VERSION 5.7 ;
  NOWIREEXTENSIONATPIN ON ;
  DIVIDERCHAR "/" ;
  BUSBITCHARS "[]" ;
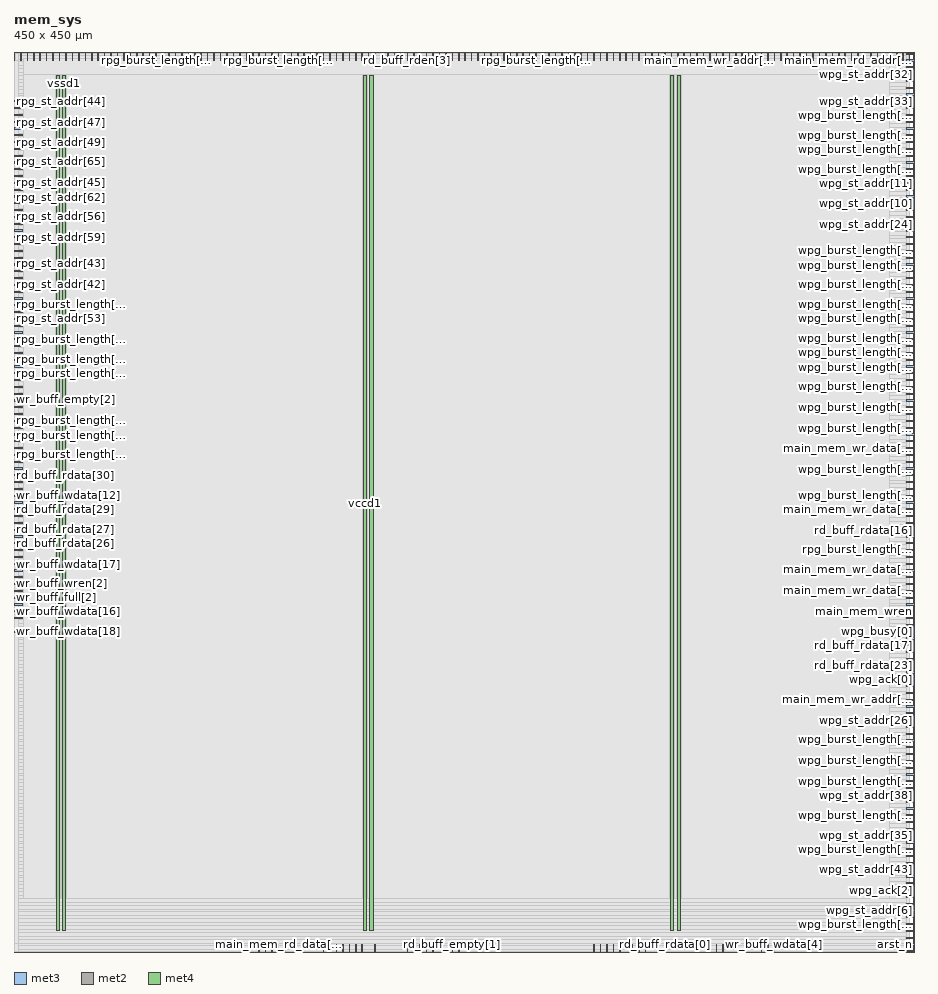
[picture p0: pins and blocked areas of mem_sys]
MACRO mem_sys
  CLASS BLOCK ;
  FOREIGN mem_sys ;
  ORIGIN 0.000 0.000 ;
  SIZE 450.000 BY 450.000 ;
  PIN arst_n
    DIRECTION INPUT ;
    USE SIGNAL ;
    ANTENNAGATEAREA 0.631200 ;
    ANTENNADIFFAREA 0.434700 ;
    PORT
      LAYER met3 ;
        RECT 446.000 0.040 450.000 0.640 ;
    END
  END arst_n
  PIN main_mem_rd_addr[0]
    DIRECTION OUTPUT ;
    USE SIGNAL ;
    ANTENNADIFFAREA 1.782000 ;
    PORT
      LAYER met2 ;
        RECT 447.670 446.000 447.950 450.000 ;
    END
  END main_mem_rd_addr[0]
  PIN main_mem_rd_addr[10]
    DIRECTION OUTPUT ;
    USE SIGNAL ;
    ANTENNADIFFAREA 1.782000 ;
    PORT
      LAYER met2 ;
        RECT 112.790 446.000 113.070 450.000 ;
    END
  END main_mem_rd_addr[10]
  PIN main_mem_rd_addr[11]
    DIRECTION OUTPUT ;
    USE SIGNAL ;
    ANTENNADIFFAREA 1.782000 ;
    PORT
      LAYER met2 ;
        RECT 61.270 446.000 61.550 450.000 ;
    END
  END main_mem_rd_addr[11]
  PIN main_mem_rd_addr[12]
    DIRECTION OUTPUT ;
    USE SIGNAL ;
    ANTENNADIFFAREA 1.782000 ;
    PORT
      LAYER met2 ;
        RECT 116.010 446.000 116.290 450.000 ;
    END
  END main_mem_rd_addr[12]
  PIN main_mem_rd_addr[13]
    DIRECTION OUTPUT ;
    USE SIGNAL ;
    ANTENNADIFFAREA 1.782000 ;
    PORT
      LAYER met2 ;
        RECT 38.730 446.000 39.010 450.000 ;
    END
  END main_mem_rd_addr[13]
  PIN main_mem_rd_addr[14]
    DIRECTION OUTPUT ;
    USE SIGNAL ;
    ANTENNADIFFAREA 1.782000 ;
    PORT
      LAYER met2 ;
        RECT 35.510 446.000 35.790 450.000 ;
    END
  END main_mem_rd_addr[14]
  PIN main_mem_rd_addr[15]
    DIRECTION OUTPUT ;
    USE SIGNAL ;
    ANTENNADIFFAREA 1.782000 ;
    PORT
      LAYER met2 ;
        RECT 412.250 446.000 412.530 450.000 ;
    END
  END main_mem_rd_addr[15]
  PIN main_mem_rd_addr[16]
    DIRECTION OUTPUT ;
    USE SIGNAL ;
    ANTENNADIFFAREA 1.782000 ;
    PORT
      LAYER met2 ;
        RECT 238.370 446.000 238.650 450.000 ;
    END
  END main_mem_rd_addr[16]
  PIN main_mem_rd_addr[1]
    DIRECTION OUTPUT ;
    USE SIGNAL ;
    ANTENNADIFFAREA 1.782000 ;
    PORT
      LAYER met2 ;
        RECT 219.050 446.000 219.330 450.000 ;
    END
  END main_mem_rd_addr[1]
  PIN main_mem_rd_addr[2]
    DIRECTION OUTPUT ;
    USE SIGNAL ;
    ANTENNADIFFAREA 1.782000 ;
    PORT
      LAYER met2 ;
        RECT 222.270 446.000 222.550 450.000 ;
    END
  END main_mem_rd_addr[2]
  PIN main_mem_rd_addr[3]
    DIRECTION OUTPUT ;
    USE SIGNAL ;
    ANTENNADIFFAREA 1.782000 ;
    PORT
      LAYER met2 ;
        RECT 135.330 446.000 135.610 450.000 ;
    END
  END main_mem_rd_addr[3]
  PIN main_mem_rd_addr[4]
    DIRECTION OUTPUT ;
    USE SIGNAL ;
    ANTENNADIFFAREA 1.782000 ;
    PORT
      LAYER met2 ;
        RECT 173.970 446.000 174.250 450.000 ;
    END
  END main_mem_rd_addr[4]
  PIN main_mem_rd_addr[5]
    DIRECTION OUTPUT ;
    USE SIGNAL ;
    ANTENNADIFFAREA 1.782000 ;
    PORT
      LAYER met2 ;
        RECT 144.990 446.000 145.270 450.000 ;
    END
  END main_mem_rd_addr[5]
  PIN main_mem_rd_addr[6]
    DIRECTION OUTPUT ;
    USE SIGNAL ;
    ANTENNADIFFAREA 1.782000 ;
    PORT
      LAYER met2 ;
        RECT 51.610 446.000 51.890 450.000 ;
    END
  END main_mem_rd_addr[6]
  PIN main_mem_rd_addr[7]
    DIRECTION OUTPUT ;
    USE SIGNAL ;
    ANTENNADIFFAREA 1.782000 ;
    PORT
      LAYER met2 ;
        RECT 141.770 446.000 142.050 450.000 ;
    END
  END main_mem_rd_addr[7]
  PIN main_mem_rd_addr[8]
    DIRECTION OUTPUT ;
    USE SIGNAL ;
    ANTENNADIFFAREA 1.782000 ;
    PORT
      LAYER met2 ;
        RECT 6.530 446.000 6.810 450.000 ;
    END
  END main_mem_rd_addr[8]
  PIN main_mem_rd_addr[9]
    DIRECTION OUTPUT ;
    USE SIGNAL ;
    ANTENNADIFFAREA 1.782000 ;
    PORT
      LAYER met2 ;
        RECT 64.490 446.000 64.770 450.000 ;
    END
  END main_mem_rd_addr[9]
  PIN main_mem_rd_data[0]
    DIRECTION INPUT ;
    USE SIGNAL ;
    ANTENNAGATEAREA 0.631200 ;
    ANTENNADIFFAREA 0.434700 ;
    PORT
      LAYER met2 ;
        RECT 167.530 0.000 167.810 4.000 ;
    END
  END main_mem_rd_data[0]
  PIN main_mem_rd_data[1]
    DIRECTION INPUT ;
    USE SIGNAL ;
    ANTENNAGATEAREA 0.631200 ;
    ANTENNADIFFAREA 0.434700 ;
    PORT
      LAYER met2 ;
        RECT 170.750 0.000 171.030 4.000 ;
    END
  END main_mem_rd_data[1]
  PIN main_mem_rd_data[2]
    DIRECTION INPUT ;
    USE SIGNAL ;
    ANTENNAGATEAREA 0.631200 ;
    ANTENNADIFFAREA 0.434700 ;
    PORT
      LAYER met2 ;
        RECT 122.450 0.000 122.730 4.000 ;
    END
  END main_mem_rd_data[2]
  PIN main_mem_rd_data[3]
    DIRECTION INPUT ;
    USE SIGNAL ;
    ANTENNAGATEAREA 0.631200 ;
    ANTENNADIFFAREA 0.434700 ;
    PORT
      LAYER met2 ;
        RECT 173.970 0.000 174.250 4.000 ;
    END
  END main_mem_rd_data[3]
  PIN main_mem_rd_data[4]
    DIRECTION INPUT ;
    USE SIGNAL ;
    ANTENNAGATEAREA 0.631200 ;
    ANTENNADIFFAREA 0.434700 ;
    PORT
      LAYER met2 ;
        RECT 125.670 0.000 125.950 4.000 ;
    END
  END main_mem_rd_data[4]
  PIN main_mem_rd_data[5]
    DIRECTION INPUT ;
    USE SIGNAL ;
    ANTENNAGATEAREA 0.631200 ;
    ANTENNADIFFAREA 0.434700 ;
    PORT
      LAYER met2 ;
        RECT 128.890 0.000 129.170 4.000 ;
    END
  END main_mem_rd_data[5]
  PIN main_mem_rd_data[6]
    DIRECTION INPUT ;
    USE SIGNAL ;
    ANTENNAGATEAREA 0.631200 ;
    ANTENNADIFFAREA 0.434700 ;
    PORT
      LAYER met2 ;
        RECT 132.110 0.000 132.390 4.000 ;
    END
  END main_mem_rd_data[6]
  PIN main_mem_rd_data[7]
    DIRECTION INPUT ;
    USE SIGNAL ;
    ANTENNAGATEAREA 0.647700 ;
    ANTENNADIFFAREA 0.434700 ;
    PORT
      LAYER met2 ;
        RECT 135.330 0.000 135.610 4.000 ;
    END
  END main_mem_rd_data[7]
  PIN main_mem_rd_data_valid
    DIRECTION INPUT ;
    USE SIGNAL ;
    ANTENNAGATEAREA 0.593700 ;
    ANTENNADIFFAREA 0.434700 ;
    PORT
      LAYER met2 ;
        RECT 170.750 446.000 171.030 450.000 ;
    END
  END main_mem_rd_data_valid
  PIN main_mem_rden
    DIRECTION OUTPUT ;
    USE SIGNAL ;
    ANTENNADIFFAREA 0.340600 ;
    PORT
      LAYER met2 ;
        RECT 444.450 446.000 444.730 450.000 ;
    END
  END main_mem_rden
  PIN main_mem_wr_addr[0]
    DIRECTION OUTPUT ;
    USE SIGNAL ;
    ANTENNADIFFAREA 1.782000 ;
    PORT
      LAYER met2 ;
        RECT 373.610 446.000 373.890 450.000 ;
    END
  END main_mem_wr_addr[0]
  PIN main_mem_wr_addr[10]
    DIRECTION OUTPUT ;
    USE SIGNAL ;
    ANTENNADIFFAREA 1.782000 ;
    PORT
      LAYER met3 ;
        RECT 446.000 370.640 450.000 371.240 ;
    END
  END main_mem_wr_addr[10]
  PIN main_mem_wr_addr[11]
    DIRECTION OUTPUT ;
    USE SIGNAL ;
    ANTENNADIFFAREA 1.782000 ;
    PORT
      LAYER met2 ;
        RECT 386.490 446.000 386.770 450.000 ;
    END
  END main_mem_wr_addr[11]
  PIN main_mem_wr_addr[12]
    DIRECTION OUTPUT ;
    USE SIGNAL ;
    ANTENNADIFFAREA 1.782000 ;
    PORT
      LAYER met2 ;
        RECT 370.390 446.000 370.670 450.000 ;
    END
  END main_mem_wr_addr[12]
  PIN main_mem_wr_addr[13]
    DIRECTION OUTPUT ;
    USE SIGNAL ;
    ANTENNADIFFAREA 1.782000 ;
    PORT
      LAYER met2 ;
        RECT 431.570 446.000 431.850 450.000 ;
    END
  END main_mem_wr_addr[13]
  PIN main_mem_wr_addr[14]
    DIRECTION OUTPUT ;
    USE SIGNAL ;
    ANTENNADIFFAREA 1.782000 ;
    PORT
      LAYER met2 ;
        RECT 421.910 446.000 422.190 450.000 ;
    END
  END main_mem_wr_addr[14]
  PIN main_mem_wr_addr[15]
    DIRECTION OUTPUT ;
    USE SIGNAL ;
    ANTENNADIFFAREA 1.782000 ;
    PORT
      LAYER met2 ;
        RECT 360.730 446.000 361.010 450.000 ;
    END
  END main_mem_wr_addr[15]
  PIN main_mem_wr_addr[16]
    DIRECTION OUTPUT ;
    USE SIGNAL ;
    ANTENNADIFFAREA 1.782000 ;
    PORT
      LAYER met2 ;
        RECT 415.470 446.000 415.750 450.000 ;
    END
  END main_mem_wr_addr[16]
  PIN main_mem_wr_addr[1]
    DIRECTION OUTPUT ;
    USE SIGNAL ;
    ANTENNADIFFAREA 1.782000 ;
    PORT
      LAYER met2 ;
        RECT 344.630 446.000 344.910 450.000 ;
    END
  END main_mem_wr_addr[1]
  PIN main_mem_wr_addr[2]
    DIRECTION OUTPUT ;
    USE SIGNAL ;
    ANTENNADIFFAREA 1.782000 ;
    PORT
      LAYER met2 ;
        RECT 351.070 446.000 351.350 450.000 ;
    END
  END main_mem_wr_addr[2]
  PIN main_mem_wr_addr[3]
    DIRECTION OUTPUT ;
    USE SIGNAL ;
    ANTENNADIFFAREA 1.782000 ;
    PORT
      LAYER met3 ;
        RECT 446.000 125.840 450.000 126.440 ;
    END
  END main_mem_wr_addr[3]
  PIN main_mem_wr_addr[4]
    DIRECTION OUTPUT ;
    USE SIGNAL ;
    ANTENNADIFFAREA 1.782000 ;
    PORT
      LAYER met3 ;
        RECT 446.000 71.440 450.000 72.040 ;
    END
  END main_mem_wr_addr[4]
  PIN main_mem_wr_addr[5]
    DIRECTION OUTPUT ;
    USE SIGNAL ;
    ANTENNADIFFAREA 1.782000 ;
    PORT
      LAYER met2 ;
        RECT 347.850 446.000 348.130 450.000 ;
    END
  END main_mem_wr_addr[5]
  PIN main_mem_wr_addr[6]
    DIRECTION OUTPUT ;
    USE SIGNAL ;
    ANTENNADIFFAREA 1.782000 ;
    PORT
      LAYER met2 ;
        RECT 341.410 446.000 341.690 450.000 ;
    END
  END main_mem_wr_addr[6]
  PIN main_mem_wr_addr[7]
    DIRECTION OUTPUT ;
    USE SIGNAL ;
    ANTENNADIFFAREA 1.782000 ;
    PORT
      LAYER met2 ;
        RECT 357.510 446.000 357.790 450.000 ;
    END
  END main_mem_wr_addr[7]
  PIN main_mem_wr_addr[8]
    DIRECTION OUTPUT ;
    USE SIGNAL ;
    ANTENNADIFFAREA 1.782000 ;
    PORT
      LAYER met2 ;
        RECT 363.950 446.000 364.230 450.000 ;
    END
  END main_mem_wr_addr[8]
  PIN main_mem_wr_addr[9]
    DIRECTION OUTPUT ;
    USE SIGNAL ;
    ANTENNADIFFAREA 1.782000 ;
    PORT
      LAYER met2 ;
        RECT 367.170 446.000 367.450 450.000 ;
    END
  END main_mem_wr_addr[9]
  PIN main_mem_wr_data[0]
    DIRECTION OUTPUT ;
    USE SIGNAL ;
    ANTENNADIFFAREA 1.782000 ;
    PORT
      LAYER met3 ;
        RECT 446.000 166.640 450.000 167.240 ;
    END
  END main_mem_wr_data[0]
  PIN main_mem_wr_data[1]
    DIRECTION OUTPUT ;
    USE SIGNAL ;
    ANTENNADIFFAREA 1.782000 ;
    PORT
      LAYER met3 ;
        RECT 446.000 180.240 450.000 180.840 ;
    END
  END main_mem_wr_data[1]
  PIN main_mem_wr_data[2]
    DIRECTION OUTPUT ;
    USE SIGNAL ;
    ANTENNADIFFAREA 1.782000 ;
    PORT
      LAYER met3 ;
        RECT 446.000 187.040 450.000 187.640 ;
    END
  END main_mem_wr_data[2]
  PIN main_mem_wr_data[3]
    DIRECTION OUTPUT ;
    USE SIGNAL ;
    ANTENNADIFFAREA 1.782000 ;
    PORT
      LAYER met3 ;
        RECT 446.000 217.640 450.000 218.240 ;
    END
  END main_mem_wr_data[3]
  PIN main_mem_wr_data[4]
    DIRECTION OUTPUT ;
    USE SIGNAL ;
    ANTENNADIFFAREA 1.782000 ;
    PORT
      LAYER met3 ;
        RECT 446.000 221.040 450.000 221.640 ;
    END
  END main_mem_wr_data[4]
  PIN main_mem_wr_data[5]
    DIRECTION OUTPUT ;
    USE SIGNAL ;
    ANTENNADIFFAREA 1.782000 ;
    PORT
      LAYER met3 ;
        RECT 446.000 255.040 450.000 255.640 ;
    END
  END main_mem_wr_data[5]
  PIN main_mem_wr_data[6]
    DIRECTION OUTPUT ;
    USE SIGNAL ;
    ANTENNADIFFAREA 1.782000 ;
    PORT
      LAYER met3 ;
        RECT 446.000 183.640 450.000 184.240 ;
    END
  END main_mem_wr_data[6]
  PIN main_mem_wr_data[7]
    DIRECTION OUTPUT ;
    USE SIGNAL ;
    ANTENNADIFFAREA 1.782000 ;
    PORT
      LAYER met3 ;
        RECT 446.000 190.440 450.000 191.040 ;
    END
  END main_mem_wr_data[7]
  PIN main_mem_wr_data_ack
    DIRECTION INPUT ;
    USE SIGNAL ;
    ANTENNAGATEAREA 0.631200 ;
    ANTENNADIFFAREA 0.434700 ;
    PORT
      LAYER met3 ;
        RECT 446.000 112.240 450.000 112.840 ;
    END
  END main_mem_wr_data_ack
  PIN main_mem_wren
    DIRECTION OUTPUT ;
    USE SIGNAL ;
    ANTENNADIFFAREA 0.340600 ;
    PORT
      LAYER met3 ;
        RECT 446.000 170.040 450.000 170.640 ;
    END
  END main_mem_wren
  PIN mem_sys_clk
    DIRECTION INPUT ;
    USE SIGNAL ;
    ANTENNAGATEAREA 0.647700 ;
    ANTENNADIFFAREA 0.434700 ;
    PORT
      LAYER met3 ;
        RECT 0.000 200.640 4.000 201.240 ;
    END
  END mem_sys_clk
  PIN rd_buff_empty[0]
    DIRECTION OUTPUT ;
    USE SIGNAL ;
    ANTENNADIFFAREA 0.340600 ;
    PORT
      LAYER met3 ;
        RECT 446.000 88.440 450.000 89.040 ;
    END
  END rd_buff_empty[0]
  PIN rd_buff_empty[1]
    DIRECTION OUTPUT ;
    USE SIGNAL ;
    ANTENNADIFFAREA 0.340600 ;
    PORT
      LAYER met2 ;
        RECT 219.050 0.000 219.330 4.000 ;
    END
  END rd_buff_empty[1]
  PIN rd_buff_empty[2]
    DIRECTION OUTPUT ;
    USE SIGNAL ;
    ANTENNADIFFAREA 0.340600 ;
    PORT
      LAYER met2 ;
        RECT 405.810 446.000 406.090 450.000 ;
    END
  END rd_buff_empty[2]
  PIN rd_buff_empty[3]
    DIRECTION OUTPUT ;
    USE SIGNAL ;
    ANTENNADIFFAREA 0.340600 ;
    PORT
      LAYER met2 ;
        RECT 209.390 446.000 209.670 450.000 ;
    END
  END rd_buff_empty[3]
  PIN rd_buff_rdata[0]
    DIRECTION OUTPUT ;
    USE SIGNAL ;
    ANTENNADIFFAREA 1.782000 ;
    PORT
      LAYER met2 ;
        RECT 325.310 0.000 325.590 4.000 ;
    END
  END rd_buff_rdata[0]
  PIN rd_buff_rdata[10]
    DIRECTION OUTPUT ;
    USE SIGNAL ;
    ANTENNADIFFAREA 1.782000 ;
    PORT
      LAYER met2 ;
        RECT 154.650 0.000 154.930 4.000 ;
    END
  END rd_buff_rdata[10]
  PIN rd_buff_rdata[11]
    DIRECTION OUTPUT ;
    USE SIGNAL ;
    ANTENNADIFFAREA 1.782000 ;
    PORT
      LAYER met2 ;
        RECT 199.730 0.000 200.010 4.000 ;
    END
  END rd_buff_rdata[11]
  PIN rd_buff_rdata[12]
    DIRECTION OUTPUT ;
    USE SIGNAL ;
    ANTENNADIFFAREA 1.782000 ;
    PORT
      LAYER met2 ;
        RECT 161.090 0.000 161.370 4.000 ;
    END
  END rd_buff_rdata[12]
  PIN rd_buff_rdata[13]
    DIRECTION OUTPUT ;
    USE SIGNAL ;
    ANTENNADIFFAREA 1.782000 ;
    PORT
      LAYER met2 ;
        RECT 202.950 0.000 203.230 4.000 ;
    END
  END rd_buff_rdata[13]
  PIN rd_buff_rdata[14]
    DIRECTION OUTPUT ;
    USE SIGNAL ;
    ANTENNADIFFAREA 1.782000 ;
    PORT
      LAYER met2 ;
        RECT 157.870 0.000 158.150 4.000 ;
    END
  END rd_buff_rdata[14]
  PIN rd_buff_rdata[15]
    DIRECTION OUTPUT ;
    USE SIGNAL ;
    ANTENNADIFFAREA 1.782000 ;
    PORT
      LAYER met2 ;
        RECT 164.310 0.000 164.590 4.000 ;
    END
  END rd_buff_rdata[15]
  PIN rd_buff_rdata[16]
    DIRECTION OUTPUT ;
    USE SIGNAL ;
    ANTENNADIFFAREA 1.782000 ;
    PORT
      LAYER met3 ;
        RECT 446.000 214.240 450.000 214.840 ;
    END
  END rd_buff_rdata[16]
  PIN rd_buff_rdata[17]
    DIRECTION OUTPUT ;
    USE SIGNAL ;
    ANTENNADIFFAREA 1.782000 ;
    PORT
      LAYER met3 ;
        RECT 446.000 153.040 450.000 153.640 ;
    END
  END rd_buff_rdata[17]
  PIN rd_buff_rdata[18]
    DIRECTION OUTPUT ;
    USE SIGNAL ;
    ANTENNADIFFAREA 1.782000 ;
    PORT
      LAYER met3 ;
        RECT 446.000 176.840 450.000 177.440 ;
    END
  END rd_buff_rdata[18]
  PIN rd_buff_rdata[19]
    DIRECTION OUTPUT ;
    USE SIGNAL ;
    ANTENNADIFFAREA 1.782000 ;
    PORT
      LAYER met3 ;
        RECT 446.000 163.240 450.000 163.840 ;
    END
  END rd_buff_rdata[19]
  PIN rd_buff_rdata[1]
    DIRECTION OUTPUT ;
    USE SIGNAL ;
    ANTENNADIFFAREA 1.782000 ;
    PORT
      LAYER met2 ;
        RECT 296.330 0.000 296.610 4.000 ;
    END
  END rd_buff_rdata[1]
  PIN rd_buff_rdata[20]
    DIRECTION OUTPUT ;
    USE SIGNAL ;
    ANTENNADIFFAREA 1.782000 ;
    PORT
      LAYER met2 ;
        RECT 289.890 0.000 290.170 4.000 ;
    END
  END rd_buff_rdata[20]
  PIN rd_buff_rdata[21]
    DIRECTION OUTPUT ;
    USE SIGNAL ;
    ANTENNADIFFAREA 1.782000 ;
    PORT
      LAYER met3 ;
        RECT 446.000 173.440 450.000 174.040 ;
    END
  END rd_buff_rdata[21]
  PIN rd_buff_rdata[22]
    DIRECTION OUTPUT ;
    USE SIGNAL ;
    ANTENNADIFFAREA 1.782000 ;
    PORT
      LAYER met3 ;
        RECT 446.000 200.640 450.000 201.240 ;
    END
  END rd_buff_rdata[22]
  PIN rd_buff_rdata[23]
    DIRECTION OUTPUT ;
    USE SIGNAL ;
    ANTENNADIFFAREA 1.782000 ;
    PORT
      LAYER met3 ;
        RECT 446.000 142.840 450.000 143.440 ;
    END
  END rd_buff_rdata[23]
  PIN rd_buff_rdata[24]
    DIRECTION OUTPUT ;
    USE SIGNAL ;
    ANTENNADIFFAREA 1.782000 ;
    PORT
      LAYER met3 ;
        RECT 0.000 234.640 4.000 235.240 ;
    END
  END rd_buff_rdata[24]
  PIN rd_buff_rdata[25]
    DIRECTION OUTPUT ;
    USE SIGNAL ;
    ANTENNADIFFAREA 1.782000 ;
    PORT
      LAYER met2 ;
        RECT 209.390 0.000 209.670 4.000 ;
    END
  END rd_buff_rdata[25]
  PIN rd_buff_rdata[26]
    DIRECTION OUTPUT ;
    USE SIGNAL ;
    ANTENNADIFFAREA 1.782000 ;
    PORT
      LAYER met3 ;
        RECT 0.000 204.040 4.000 204.640 ;
    END
  END rd_buff_rdata[26]
  PIN rd_buff_rdata[27]
    DIRECTION OUTPUT ;
    USE SIGNAL ;
    ANTENNADIFFAREA 1.782000 ;
    PORT
      LAYER met3 ;
        RECT 0.000 207.440 4.000 208.040 ;
    END
  END rd_buff_rdata[27]
  PIN rd_buff_rdata[28]
    DIRECTION OUTPUT ;
    USE SIGNAL ;
    ANTENNADIFFAREA 1.782000 ;
    PORT
      LAYER met3 ;
        RECT 0.000 183.640 4.000 184.240 ;
    END
  END rd_buff_rdata[28]
  PIN rd_buff_rdata[29]
    DIRECTION OUTPUT ;
    USE SIGNAL ;
    ANTENNADIFFAREA 1.782000 ;
    PORT
      LAYER met3 ;
        RECT 0.000 221.040 4.000 221.640 ;
    END
  END rd_buff_rdata[29]
  PIN rd_buff_rdata[2]
    DIRECTION OUTPUT ;
    USE SIGNAL ;
    ANTENNADIFFAREA 1.782000 ;
    PORT
      LAYER met2 ;
        RECT 299.550 0.000 299.830 4.000 ;
    END
  END rd_buff_rdata[2]
  PIN rd_buff_rdata[30]
    DIRECTION OUTPUT ;
    USE SIGNAL ;
    ANTENNADIFFAREA 1.782000 ;
    PORT
      LAYER met3 ;
        RECT 0.000 238.040 4.000 238.640 ;
    END
  END rd_buff_rdata[30]
  PIN rd_buff_rdata[31]
    DIRECTION OUTPUT ;
    USE SIGNAL ;
    ANTENNADIFFAREA 1.782000 ;
    PORT
      LAYER met2 ;
        RECT 206.170 0.000 206.450 4.000 ;
    END
  END rd_buff_rdata[31]
  PIN rd_buff_rdata[3]
    DIRECTION OUTPUT ;
    USE SIGNAL ;
    ANTENNADIFFAREA 1.782000 ;
    PORT
      LAYER met2 ;
        RECT 312.430 0.000 312.710 4.000 ;
    END
  END rd_buff_rdata[3]
  PIN rd_buff_rdata[4]
    DIRECTION OUTPUT ;
    USE SIGNAL ;
    ANTENNADIFFAREA 1.782000 ;
    PORT
      LAYER met2 ;
        RECT 309.210 0.000 309.490 4.000 ;
    END
  END rd_buff_rdata[4]
  PIN rd_buff_rdata[5]
    DIRECTION OUTPUT ;
    USE SIGNAL ;
    ANTENNADIFFAREA 1.782000 ;
    PORT
      LAYER met2 ;
        RECT 302.770 0.000 303.050 4.000 ;
    END
  END rd_buff_rdata[5]
  PIN rd_buff_rdata[6]
    DIRECTION OUTPUT ;
    USE SIGNAL ;
    ANTENNADIFFAREA 1.782000 ;
    PORT
      LAYER met2 ;
        RECT 293.110 0.000 293.390 4.000 ;
    END
  END rd_buff_rdata[6]
  PIN rd_buff_rdata[7]
    DIRECTION OUTPUT ;
    USE SIGNAL ;
    ANTENNADIFFAREA 1.782000 ;
    PORT
      LAYER met2 ;
        RECT 315.650 0.000 315.930 4.000 ;
    END
  END rd_buff_rdata[7]
  PIN rd_buff_rdata[8]
    DIRECTION OUTPUT ;
    USE SIGNAL ;
    ANTENNADIFFAREA 1.782000 ;
    PORT
      LAYER met2 ;
        RECT 180.410 0.000 180.690 4.000 ;
    END
  END rd_buff_rdata[8]
  PIN rd_buff_rdata[9]
    DIRECTION OUTPUT ;
    USE SIGNAL ;
    ANTENNADIFFAREA 1.782000 ;
    PORT
      LAYER met2 ;
        RECT 196.510 0.000 196.790 4.000 ;
    END
  END rd_buff_rdata[9]
  PIN rd_buff_rden[0]
    DIRECTION INPUT ;
    USE SIGNAL ;
    ANTENNAGATEAREA 0.560700 ;
    ANTENNADIFFAREA 0.434700 ;
    PORT
      LAYER met3 ;
        RECT 446.000 47.640 450.000 48.240 ;
    END
  END rd_buff_rden[0]
  PIN rd_buff_rden[1]
    DIRECTION INPUT ;
    USE SIGNAL ;
    ANTENNAGATEAREA 0.560700 ;
    ANTENNADIFFAREA 0.434700 ;
    PORT
      LAYER met2 ;
        RECT 222.270 0.000 222.550 4.000 ;
    END
  END rd_buff_rden[1]
  PIN rd_buff_rden[2]
    DIRECTION INPUT ;
    USE SIGNAL ;
    ANTENNAGATEAREA 0.560700 ;
    ANTENNADIFFAREA 0.434700 ;
    PORT
      LAYER met2 ;
        RECT 441.230 446.000 441.510 450.000 ;
    END
  END rd_buff_rden[2]
  PIN rd_buff_rden[3]
    DIRECTION INPUT ;
    USE SIGNAL ;
    ANTENNAGATEAREA 0.560700 ;
    ANTENNADIFFAREA 0.434700 ;
    PORT
      LAYER met2 ;
        RECT 196.510 446.000 196.790 450.000 ;
    END
  END rd_buff_rden[3]
  PIN rpg_ack[0]
    DIRECTION OUTPUT ;
    USE SIGNAL ;
    ANTENNADIFFAREA 0.340600 ;
    PORT
      LAYER met2 ;
        RECT 425.130 446.000 425.410 450.000 ;
    END
  END rpg_ack[0]
  PIN rpg_ack[1]
    DIRECTION OUTPUT ;
    USE SIGNAL ;
    ANTENNADIFFAREA 0.340600 ;
    PORT
      LAYER met2 ;
        RECT 331.750 446.000 332.030 450.000 ;
    END
  END rpg_ack[1]
  PIN rpg_ack[2]
    DIRECTION OUTPUT ;
    USE SIGNAL ;
    ANTENNADIFFAREA 0.340600 ;
    PORT
      LAYER met2 ;
        RECT 206.170 446.000 206.450 450.000 ;
    END
  END rpg_ack[2]
  PIN rpg_ack[3]
    DIRECTION OUTPUT ;
    USE SIGNAL ;
    ANTENNADIFFAREA 0.340600 ;
    PORT
      LAYER met2 ;
        RECT 215.830 446.000 216.110 450.000 ;
    END
  END rpg_ack[3]
  PIN rpg_burst_length[0]
    DIRECTION INPUT ;
    USE SIGNAL ;
    ANTENNAGATEAREA 0.560700 ;
    ANTENNADIFFAREA 0.434700 ;
    PORT
      LAYER met2 ;
        RECT 438.010 446.000 438.290 450.000 ;
    END
  END rpg_burst_length[0]
  PIN rpg_burst_length[10]
    DIRECTION INPUT ;
    USE SIGNAL ;
    ANTENNAGATEAREA 0.560700 ;
    ANTENNADIFFAREA 0.434700 ;
    PORT
      LAYER met3 ;
        RECT 446.000 197.240 450.000 197.840 ;
    END
  END rpg_burst_length[10]
  PIN rpg_burst_length[11]
    DIRECTION INPUT ;
    USE SIGNAL ;
    ANTENNAGATEAREA 0.560700 ;
    ANTENNADIFFAREA 0.434700 ;
    PORT
      LAYER met2 ;
        RECT 318.870 446.000 319.150 450.000 ;
    END
  END rpg_burst_length[11]
  PIN rpg_burst_length[12]
    DIRECTION INPUT ;
    USE SIGNAL ;
    ANTENNAGATEAREA 0.560700 ;
    ANTENNADIFFAREA 0.434700 ;
    PORT
      LAYER met2 ;
        RECT 286.670 446.000 286.950 450.000 ;
    END
  END rpg_burst_length[12]
  PIN rpg_burst_length[13]
    DIRECTION INPUT ;
    USE SIGNAL ;
    ANTENNAGATEAREA 0.560700 ;
    ANTENNADIFFAREA 0.434700 ;
    PORT
      LAYER met2 ;
        RECT 325.310 446.000 325.590 450.000 ;
    END
  END rpg_burst_length[13]
  PIN rpg_burst_length[14]
    DIRECTION INPUT ;
    USE SIGNAL ;
    ANTENNAGATEAREA 0.560700 ;
    ANTENNADIFFAREA 0.434700 ;
    PORT
      LAYER met2 ;
        RECT 315.650 446.000 315.930 450.000 ;
    END
  END rpg_burst_length[14]
  PIN rpg_burst_length[15]
    DIRECTION INPUT ;
    USE SIGNAL ;
    ANTENNAGATEAREA 0.560700 ;
    ANTENNADIFFAREA 0.434700 ;
    PORT
      LAYER met2 ;
        RECT 302.770 446.000 303.050 450.000 ;
    END
  END rpg_burst_length[15]
  PIN rpg_burst_length[16]
    DIRECTION INPUT ;
    USE SIGNAL ;
    ANTENNAGATEAREA 0.560700 ;
    ANTENNADIFFAREA 0.434700 ;
    PORT
      LAYER met2 ;
        RECT 376.830 446.000 377.110 450.000 ;
    END
  END rpg_burst_length[16]
  PIN rpg_burst_length[17]
    DIRECTION INPUT ;
    USE SIGNAL ;
    ANTENNAGATEAREA 0.560700 ;
    ANTENNADIFFAREA 0.434700 ;
    PORT
      LAYER met2 ;
        RECT 409.030 446.000 409.310 450.000 ;
    END
  END rpg_burst_length[17]
  PIN rpg_burst_length[18]
    DIRECTION INPUT ;
    USE SIGNAL ;
    ANTENNAGATEAREA 0.560700 ;
    ANTENNADIFFAREA 0.434700 ;
    PORT
      LAYER met2 ;
        RECT 254.470 446.000 254.750 450.000 ;
    END
  END rpg_burst_length[18]
  PIN rpg_burst_length[19]
    DIRECTION INPUT ;
    USE SIGNAL ;
    ANTENNAGATEAREA 0.560700 ;
    ANTENNADIFFAREA 0.434700 ;
    PORT
      LAYER met2 ;
        RECT 244.810 446.000 245.090 450.000 ;
    END
  END rpg_burst_length[19]
  PIN rpg_burst_length[1]
    DIRECTION INPUT ;
    USE SIGNAL ;
    ANTENNAGATEAREA 0.560700 ;
    ANTENNADIFFAREA 0.434700 ;
    PORT
      LAYER met2 ;
        RECT 392.930 446.000 393.210 450.000 ;
    END
  END rpg_burst_length[1]
  PIN rpg_burst_length[20]
    DIRECTION INPUT ;
    USE SIGNAL ;
    ANTENNAGATEAREA 0.560700 ;
    ANTENNADIFFAREA 0.434700 ;
    PORT
      LAYER met2 ;
        RECT 354.290 446.000 354.570 450.000 ;
    END
  END rpg_burst_length[20]
  PIN rpg_burst_length[21]
    DIRECTION INPUT ;
    USE SIGNAL ;
    ANTENNAGATEAREA 0.560700 ;
    ANTENNADIFFAREA 0.434700 ;
    PORT
      LAYER met2 ;
        RECT 248.030 446.000 248.310 450.000 ;
    END
  END rpg_burst_length[21]
  PIN rpg_burst_length[22]
    DIRECTION INPUT ;
    USE SIGNAL ;
    ANTENNAGATEAREA 0.560700 ;
    ANTENNADIFFAREA 0.434700 ;
    PORT
      LAYER met2 ;
        RECT 257.690 446.000 257.970 450.000 ;
    END
  END rpg_burst_length[22]
  PIN rpg_burst_length[23]
    DIRECTION INPUT ;
    USE SIGNAL ;
    ANTENNAGATEAREA 0.560700 ;
    ANTENNADIFFAREA 0.434700 ;
    PORT
      LAYER met2 ;
        RECT 270.570 446.000 270.850 450.000 ;
    END
  END rpg_burst_length[23]
  PIN rpg_burst_length[24]
    DIRECTION INPUT ;
    USE SIGNAL ;
    ANTENNAGATEAREA 0.560700 ;
    ANTENNADIFFAREA 0.434700 ;
    PORT
      LAYER met2 ;
        RECT 277.010 446.000 277.290 450.000 ;
    END
  END rpg_burst_length[24]
  PIN rpg_burst_length[25]
    DIRECTION INPUT ;
    USE SIGNAL ;
    ANTENNAGATEAREA 0.560700 ;
    ANTENNADIFFAREA 0.434700 ;
    PORT
      LAYER met2 ;
        RECT 260.910 446.000 261.190 450.000 ;
    END
  END rpg_burst_length[25]
  PIN rpg_burst_length[26]
    DIRECTION INPUT ;
    USE SIGNAL ;
    ANTENNAGATEAREA 0.560700 ;
    ANTENNADIFFAREA 0.434700 ;
    PORT
      LAYER met2 ;
        RECT 289.890 446.000 290.170 450.000 ;
    END
  END rpg_burst_length[26]
  PIN rpg_burst_length[27]
    DIRECTION INPUT ;
    USE SIGNAL ;
    ANTENNAGATEAREA 0.560700 ;
    ANTENNADIFFAREA 0.434700 ;
    PORT
      LAYER met2 ;
        RECT 267.350 446.000 267.630 450.000 ;
    END
  END rpg_burst_length[27]
  PIN rpg_burst_length[28]
    DIRECTION INPUT ;
    USE SIGNAL ;
    ANTENNAGATEAREA 0.560700 ;
    ANTENNADIFFAREA 0.434700 ;
    PORT
      LAYER met2 ;
        RECT 264.130 446.000 264.410 450.000 ;
    END
  END rpg_burst_length[28]
  PIN rpg_burst_length[29]
    DIRECTION INPUT ;
    USE SIGNAL ;
    ANTENNAGATEAREA 0.560700 ;
    ANTENNADIFFAREA 0.434700 ;
    PORT
      LAYER met2 ;
        RECT 280.230 446.000 280.510 450.000 ;
    END
  END rpg_burst_length[29]
  PIN rpg_burst_length[2]
    DIRECTION INPUT ;
    USE SIGNAL ;
    ANTENNAGATEAREA 0.560700 ;
    ANTENNADIFFAREA 0.434700 ;
    PORT
      LAYER met2 ;
        RECT 322.090 446.000 322.370 450.000 ;
    END
  END rpg_burst_length[2]
  PIN rpg_burst_length[30]
    DIRECTION INPUT ;
    USE SIGNAL ;
    ANTENNAGATEAREA 0.560700 ;
    ANTENNADIFFAREA 0.434700 ;
    PORT
      LAYER met2 ;
        RECT 283.450 446.000 283.730 450.000 ;
    END
  END rpg_burst_length[30]
  PIN rpg_burst_length[31]
    DIRECTION INPUT ;
    USE SIGNAL ;
    ANTENNAGATEAREA 0.560700 ;
    ANTENNADIFFAREA 0.434700 ;
    PORT
      LAYER met2 ;
        RECT 293.110 446.000 293.390 450.000 ;
    END
  END rpg_burst_length[31]
  PIN rpg_burst_length[32]
    DIRECTION INPUT ;
    USE SIGNAL ;
    ANTENNAGATEAREA 0.560700 ;
    ANTENNADIFFAREA 0.434700 ;
    PORT
      LAYER met2 ;
        RECT 273.790 446.000 274.070 450.000 ;
    END
  END rpg_burst_length[32]
  PIN rpg_burst_length[33]
    DIRECTION INPUT ;
    USE SIGNAL ;
    ANTENNAGATEAREA 0.560700 ;
    ANTENNADIFFAREA 0.434700 ;
    PORT
      LAYER met2 ;
        RECT 305.990 446.000 306.270 450.000 ;
    END
  END rpg_burst_length[33]
  PIN rpg_burst_length[34]
    DIRECTION INPUT ;
    USE SIGNAL ;
    ANTENNAGATEAREA 0.560700 ;
    ANTENNADIFFAREA 0.434700 ;
    PORT
      LAYER met2 ;
        RECT 199.730 446.000 200.010 450.000 ;
    END
  END rpg_burst_length[34]
  PIN rpg_burst_length[35]
    DIRECTION INPUT ;
    USE SIGNAL ;
    ANTENNAGATEAREA 0.560700 ;
    ANTENNADIFFAREA 0.434700 ;
    PORT
      LAYER met2 ;
        RECT 193.290 446.000 193.570 450.000 ;
    END
  END rpg_burst_length[35]
  PIN rpg_burst_length[36]
    DIRECTION INPUT ;
    USE SIGNAL ;
    ANTENNAGATEAREA 0.560700 ;
    ANTENNADIFFAREA 0.434700 ;
    PORT
      LAYER met2 ;
        RECT 138.550 446.000 138.830 450.000 ;
    END
  END rpg_burst_length[36]
  PIN rpg_burst_length[37]
    DIRECTION INPUT ;
    USE SIGNAL ;
    ANTENNAGATEAREA 0.560700 ;
    ANTENNADIFFAREA 0.434700 ;
    PORT
      LAYER met3 ;
        RECT 0.000 248.240 4.000 248.840 ;
    END
  END rpg_burst_length[37]
  PIN rpg_burst_length[38]
    DIRECTION INPUT ;
    USE SIGNAL ;
    ANTENNAGATEAREA 0.560700 ;
    ANTENNADIFFAREA 0.434700 ;
    PORT
      LAYER met3 ;
        RECT 0.000 261.840 4.000 262.440 ;
    END
  END rpg_burst_length[38]
  PIN rpg_burst_length[39]
    DIRECTION INPUT ;
    USE SIGNAL ;
    ANTENNAGATEAREA 0.560700 ;
    ANTENNADIFFAREA 0.434700 ;
    PORT
      LAYER met2 ;
        RECT 106.350 446.000 106.630 450.000 ;
    END
  END rpg_burst_length[39]
  PIN rpg_burst_length[3]
    DIRECTION INPUT ;
    USE SIGNAL ;
    ANTENNAGATEAREA 0.560700 ;
    ANTENNADIFFAREA 0.434700 ;
    PORT
      LAYER met2 ;
        RECT 328.530 446.000 328.810 450.000 ;
    END
  END rpg_burst_length[3]
  PIN rpg_burst_length[40]
    DIRECTION INPUT ;
    USE SIGNAL ;
    ANTENNAGATEAREA 0.560700 ;
    ANTENNADIFFAREA 0.434700 ;
    PORT
      LAYER met3 ;
        RECT 0.000 292.440 4.000 293.040 ;
    END
  END rpg_burst_length[40]
  PIN rpg_burst_length[41]
    DIRECTION INPUT ;
    USE SIGNAL ;
    ANTENNAGATEAREA 0.560700 ;
    ANTENNADIFFAREA 0.434700 ;
    PORT
      LAYER met3 ;
        RECT 0.000 289.040 4.000 289.640 ;
    END
  END rpg_burst_length[41]
  PIN rpg_burst_length[42]
    DIRECTION INPUT ;
    USE SIGNAL ;
    ANTENNAGATEAREA 0.560700 ;
    ANTENNADIFFAREA 0.434700 ;
    PORT
      LAYER met2 ;
        RECT 32.290 446.000 32.570 450.000 ;
    END
  END rpg_burst_length[42]
  PIN rpg_burst_length[43]
    DIRECTION INPUT ;
    USE SIGNAL ;
    ANTENNAGATEAREA 0.560700 ;
    ANTENNADIFFAREA 0.434700 ;
    PORT
      LAYER met3 ;
        RECT 0.000 306.040 4.000 306.640 ;
    END
  END rpg_burst_length[43]
  PIN rpg_burst_length[44]
    DIRECTION INPUT ;
    USE SIGNAL ;
    ANTENNAGATEAREA 0.560700 ;
    ANTENNADIFFAREA 0.434700 ;
    PORT
      LAYER met2 ;
        RECT 80.590 446.000 80.870 450.000 ;
    END
  END rpg_burst_length[44]
  PIN rpg_burst_length[45]
    DIRECTION INPUT ;
    USE SIGNAL ;
    ANTENNAGATEAREA 0.560700 ;
    ANTENNADIFFAREA 0.434700 ;
    PORT
      LAYER met2 ;
        RECT 164.310 446.000 164.590 450.000 ;
    END
  END rpg_burst_length[45]
  PIN rpg_burst_length[46]
    DIRECTION INPUT ;
    USE SIGNAL ;
    ANTENNAGATEAREA 0.560700 ;
    ANTENNADIFFAREA 0.434700 ;
    PORT
      LAYER met3 ;
        RECT 0.000 265.240 4.000 265.840 ;
    END
  END rpg_burst_length[46]
  PIN rpg_burst_length[47]
    DIRECTION INPUT ;
    USE SIGNAL ;
    ANTENNAGATEAREA 0.560700 ;
    ANTENNADIFFAREA 0.434700 ;
    PORT
      LAYER met3 ;
        RECT 0.000 268.640 4.000 269.240 ;
    END
  END rpg_burst_length[47]
  PIN rpg_burst_length[48]
    DIRECTION INPUT ;
    USE SIGNAL ;
    ANTENNAGATEAREA 0.560700 ;
    ANTENNADIFFAREA 0.434700 ;
    PORT
      LAYER met3 ;
        RECT 0.000 275.440 4.000 276.040 ;
    END
  END rpg_burst_length[48]
  PIN rpg_burst_length[49]
    DIRECTION INPUT ;
    USE SIGNAL ;
    ANTENNAGATEAREA 0.560700 ;
    ANTENNADIFFAREA 0.434700 ;
    PORT
      LAYER met2 ;
        RECT 167.530 446.000 167.810 450.000 ;
    END
  END rpg_burst_length[49]
  PIN rpg_burst_length[4]
    DIRECTION INPUT ;
    USE SIGNAL ;
    ANTENNAGATEAREA 0.560700 ;
    ANTENNADIFFAREA 0.434700 ;
    PORT
      LAYER met2 ;
        RECT 309.210 446.000 309.490 450.000 ;
    END
  END rpg_burst_length[4]
  PIN rpg_burst_length[50]
    DIRECTION INPUT ;
    USE SIGNAL ;
    ANTENNAGATEAREA 0.560700 ;
    ANTENNADIFFAREA 0.434700 ;
    PORT
      LAYER met2 ;
        RECT 180.410 446.000 180.690 450.000 ;
    END
  END rpg_burst_length[50]
  PIN rpg_burst_length[51]
    DIRECTION INPUT ;
    USE SIGNAL ;
    ANTENNAGATEAREA 0.560700 ;
    ANTENNADIFFAREA 0.434700 ;
    PORT
      LAYER met2 ;
        RECT 132.110 446.000 132.390 450.000 ;
    END
  END rpg_burst_length[51]
  PIN rpg_burst_length[52]
    DIRECTION INPUT ;
    USE SIGNAL ;
    ANTENNAGATEAREA 0.995400 ;
    ANTENNADIFFAREA 0.869400 ;
    PORT
      LAYER met2 ;
        RECT 3.310 446.000 3.590 450.000 ;
    END
  END rpg_burst_length[52]
  PIN rpg_burst_length[53]
    DIRECTION INPUT ;
    USE SIGNAL ;
    ANTENNAGATEAREA 0.995400 ;
    ANTENNADIFFAREA 0.869400 ;
    PORT
      LAYER met2 ;
        RECT 48.390 446.000 48.670 450.000 ;
    END
  END rpg_burst_length[53]
  PIN rpg_burst_length[54]
    DIRECTION INPUT ;
    USE SIGNAL ;
    ANTENNAGATEAREA 0.560700 ;
    ANTENNADIFFAREA 0.434700 ;
    PORT
      LAYER met2 ;
        RECT 83.810 446.000 84.090 450.000 ;
    END
  END rpg_burst_length[54]
  PIN rpg_burst_length[55]
    DIRECTION INPUT ;
    USE SIGNAL ;
    ANTENNAGATEAREA 0.995400 ;
    ANTENNADIFFAREA 0.869400 ;
    PORT
      LAYER met2 ;
        RECT 96.690 446.000 96.970 450.000 ;
    END
  END rpg_burst_length[55]
  PIN rpg_burst_length[56]
    DIRECTION INPUT ;
    USE SIGNAL ;
    ANTENNAGATEAREA 0.560700 ;
    ANTENNADIFFAREA 0.434700 ;
    PORT
      LAYER met2 ;
        RECT 93.470 446.000 93.750 450.000 ;
    END
  END rpg_burst_length[56]
  PIN rpg_burst_length[57]
    DIRECTION INPUT ;
    USE SIGNAL ;
    ANTENNAGATEAREA 0.560700 ;
    ANTENNADIFFAREA 0.434700 ;
    PORT
      LAYER met2 ;
        RECT 128.890 446.000 129.170 450.000 ;
    END
  END rpg_burst_length[57]
  PIN rpg_burst_length[58]
    DIRECTION INPUT ;
    USE SIGNAL ;
    ANTENNAGATEAREA 0.560700 ;
    ANTENNADIFFAREA 0.434700 ;
    PORT
      LAYER met2 ;
        RECT 125.670 446.000 125.950 450.000 ;
    END
  END rpg_burst_length[58]
  PIN rpg_burst_length[59]
    DIRECTION INPUT ;
    USE SIGNAL ;
    ANTENNAGATEAREA 0.560700 ;
    ANTENNADIFFAREA 0.434700 ;
    PORT
      LAYER met2 ;
        RECT 119.230 446.000 119.510 450.000 ;
    END
  END rpg_burst_length[59]
  PIN rpg_burst_length[5]
    DIRECTION INPUT ;
    USE SIGNAL ;
    ANTENNAGATEAREA 0.560700 ;
    ANTENNADIFFAREA 0.434700 ;
    PORT
      LAYER met2 ;
        RECT 296.330 446.000 296.610 450.000 ;
    END
  END rpg_burst_length[5]
  PIN rpg_burst_length[60]
    DIRECTION INPUT ;
    USE SIGNAL ;
    ANTENNAGATEAREA 0.560700 ;
    ANTENNADIFFAREA 0.434700 ;
    PORT
      LAYER met2 ;
        RECT 45.170 446.000 45.450 450.000 ;
    END
  END rpg_burst_length[60]
  PIN rpg_burst_length[61]
    DIRECTION INPUT ;
    USE SIGNAL ;
    ANTENNAGATEAREA 0.560700 ;
    ANTENNADIFFAREA 0.434700 ;
    PORT
      LAYER met3 ;
        RECT 0.000 312.840 4.000 313.440 ;
    END
  END rpg_burst_length[61]
  PIN rpg_burst_length[62]
    DIRECTION INPUT ;
    USE SIGNAL ;
    ANTENNAGATEAREA 0.560700 ;
    ANTENNADIFFAREA 0.434700 ;
    PORT
      LAYER met3 ;
        RECT 0.000 319.640 4.000 320.240 ;
    END
  END rpg_burst_length[62]
  PIN rpg_burst_length[63]
    DIRECTION INPUT ;
    USE SIGNAL ;
    ANTENNAGATEAREA 0.560700 ;
    ANTENNADIFFAREA 0.434700 ;
    PORT
      LAYER met2 ;
        RECT 70.930 446.000 71.210 450.000 ;
    END
  END rpg_burst_length[63]
  PIN rpg_burst_length[64]
    DIRECTION INPUT ;
    USE SIGNAL ;
    ANTENNAGATEAREA 0.560700 ;
    ANTENNADIFFAREA 0.434700 ;
    PORT
      LAYER met2 ;
        RECT 109.570 446.000 109.850 450.000 ;
    END
  END rpg_burst_length[64]
  PIN rpg_burst_length[65]
    DIRECTION INPUT ;
    USE SIGNAL ;
    ANTENNAGATEAREA 0.560700 ;
    ANTENNADIFFAREA 0.434700 ;
    PORT
      LAYER met2 ;
        RECT 103.130 446.000 103.410 450.000 ;
    END
  END rpg_burst_length[65]
  PIN rpg_burst_length[66]
    DIRECTION INPUT ;
    USE SIGNAL ;
    ANTENNAGATEAREA 0.560700 ;
    ANTENNADIFFAREA 0.434700 ;
    PORT
      LAYER met2 ;
        RECT 0.090 446.000 0.370 450.000 ;
    END
  END rpg_burst_length[66]
  PIN rpg_burst_length[67]
    DIRECTION INPUT ;
    USE SIGNAL ;
    ANTENNAGATEAREA 0.560700 ;
    ANTENNADIFFAREA 0.434700 ;
    PORT
      LAYER met2 ;
        RECT 54.830 446.000 55.110 450.000 ;
    END
  END rpg_burst_length[67]
  PIN rpg_burst_length[6]
    DIRECTION INPUT ;
    USE SIGNAL ;
    ANTENNAGATEAREA 0.560700 ;
    ANTENNADIFFAREA 0.434700 ;
    PORT
      LAYER met2 ;
        RECT 299.550 446.000 299.830 450.000 ;
    END
  END rpg_burst_length[6]
  PIN rpg_burst_length[7]
    DIRECTION INPUT ;
    USE SIGNAL ;
    ANTENNAGATEAREA 0.560700 ;
    ANTENNADIFFAREA 0.434700 ;
    PORT
      LAYER met2 ;
        RECT 312.430 446.000 312.710 450.000 ;
    END
  END rpg_burst_length[7]
  PIN rpg_burst_length[8]
    DIRECTION INPUT ;
    USE SIGNAL ;
    ANTENNAGATEAREA 0.560700 ;
    ANTENNADIFFAREA 0.434700 ;
    PORT
      LAYER met2 ;
        RECT 383.270 446.000 383.550 450.000 ;
    END
  END rpg_burst_length[8]
  PIN rpg_burst_length[9]
    DIRECTION INPUT ;
    USE SIGNAL ;
    ANTENNAGATEAREA 0.560700 ;
    ANTENNADIFFAREA 0.434700 ;
    PORT
      LAYER met2 ;
        RECT 399.370 446.000 399.650 450.000 ;
    END
  END rpg_burst_length[9]
  PIN rpg_burst_ongoing[0]
    DIRECTION OUTPUT ;
    USE SIGNAL ;
    ANTENNADIFFAREA 0.340600 ;
    PORT
      LAYER met2 ;
        RECT 389.710 446.000 389.990 450.000 ;
    END
  END rpg_burst_ongoing[0]
  PIN rpg_burst_ongoing[1]
    DIRECTION OUTPUT ;
    USE SIGNAL ;
    ANTENNADIFFAREA 0.340600 ;
    PORT
      LAYER met2 ;
        RECT 380.050 446.000 380.330 450.000 ;
    END
  END rpg_burst_ongoing[1]
  PIN rpg_burst_ongoing[2]
    DIRECTION OUTPUT ;
    USE SIGNAL ;
    ANTENNADIFFAREA 0.340600 ;
    PORT
      LAYER met2 ;
        RECT 202.950 446.000 203.230 450.000 ;
    END
  END rpg_burst_ongoing[2]
  PIN rpg_burst_ongoing[3]
    DIRECTION OUTPUT ;
    USE SIGNAL ;
    ANTENNADIFFAREA 0.340600 ;
    PORT
      LAYER met2 ;
        RECT 157.870 446.000 158.150 450.000 ;
    END
  END rpg_burst_ongoing[3]
  PIN rpg_busy[0]
    DIRECTION INPUT ;
    USE SIGNAL ;
    ANTENNAGATEAREA 0.560700 ;
    ANTENNADIFFAREA 0.434700 ;
    PORT
      LAYER met2 ;
        RECT 434.790 446.000 435.070 450.000 ;
    END
  END rpg_busy[0]
  PIN rpg_busy[1]
    DIRECTION INPUT ;
    USE SIGNAL ;
    ANTENNAGATEAREA 0.560700 ;
    ANTENNADIFFAREA 0.434700 ;
    PORT
      LAYER met2 ;
        RECT 235.150 446.000 235.430 450.000 ;
    END
  END rpg_busy[1]
  PIN rpg_busy[2]
    DIRECTION INPUT ;
    USE SIGNAL ;
    ANTENNAGATEAREA 0.560700 ;
    ANTENNADIFFAREA 0.434700 ;
    PORT
      LAYER met2 ;
        RECT 186.850 446.000 187.130 450.000 ;
    END
  END rpg_busy[2]
  PIN rpg_busy[3]
    DIRECTION INPUT ;
    USE SIGNAL ;
    ANTENNAGATEAREA 0.560700 ;
    ANTENNADIFFAREA 0.434700 ;
    PORT
      LAYER met2 ;
        RECT 87.030 446.000 87.310 450.000 ;
    END
  END rpg_busy[3]
  PIN rpg_st_addr[0]
    DIRECTION INPUT ;
    USE SIGNAL ;
    ANTENNAGATEAREA 0.560700 ;
    ANTENNADIFFAREA 0.434700 ;
    PORT
      LAYER met2 ;
        RECT 402.590 446.000 402.870 450.000 ;
    END
  END rpg_st_addr[0]
  PIN rpg_st_addr[10]
    DIRECTION INPUT ;
    USE SIGNAL ;
    ANTENNAGATEAREA 0.560700 ;
    ANTENNADIFFAREA 0.434700 ;
    PORT
      LAYER met2 ;
        RECT 177.190 446.000 177.470 450.000 ;
    END
  END rpg_st_addr[10]
  PIN rpg_st_addr[11]
    DIRECTION INPUT ;
    USE SIGNAL ;
    ANTENNAGATEAREA 0.560700 ;
    ANTENNADIFFAREA 0.434700 ;
    PORT
      LAYER met2 ;
        RECT 183.630 446.000 183.910 450.000 ;
    END
  END rpg_st_addr[11]
  PIN rpg_st_addr[12]
    DIRECTION INPUT ;
    USE SIGNAL ;
    ANTENNAGATEAREA 0.560700 ;
    ANTENNADIFFAREA 0.434700 ;
    PORT
      LAYER met2 ;
        RECT 151.430 446.000 151.710 450.000 ;
    END
  END rpg_st_addr[12]
  PIN rpg_st_addr[13]
    DIRECTION INPUT ;
    USE SIGNAL ;
    ANTENNAGATEAREA 0.560700 ;
    ANTENNADIFFAREA 0.434700 ;
    PORT
      LAYER met2 ;
        RECT 19.410 446.000 19.690 450.000 ;
    END
  END rpg_st_addr[13]
  PIN rpg_st_addr[14]
    DIRECTION INPUT ;
    USE SIGNAL ;
    ANTENNAGATEAREA 0.560700 ;
    ANTENNADIFFAREA 0.434700 ;
    PORT
      LAYER met2 ;
        RECT 396.150 446.000 396.430 450.000 ;
    END
  END rpg_st_addr[14]
  PIN rpg_st_addr[15]
    DIRECTION INPUT ;
    USE SIGNAL ;
    ANTENNAGATEAREA 0.560700 ;
    ANTENNADIFFAREA 0.434700 ;
    PORT
      LAYER met2 ;
        RECT 334.970 446.000 335.250 450.000 ;
    END
  END rpg_st_addr[15]
  PIN rpg_st_addr[16]
    DIRECTION INPUT ;
    USE SIGNAL ;
    ANTENNAGATEAREA 0.560700 ;
    ANTENNADIFFAREA 0.434700 ;
    PORT
      LAYER met2 ;
        RECT 251.250 446.000 251.530 450.000 ;
    END
  END rpg_st_addr[16]
  PIN rpg_st_addr[17]
    DIRECTION INPUT ;
    USE SIGNAL ;
    ANTENNAGATEAREA 0.560700 ;
    ANTENNADIFFAREA 0.434700 ;
    PORT
      LAYER met2 ;
        RECT 241.590 446.000 241.870 450.000 ;
    END
  END rpg_st_addr[17]
  PIN rpg_st_addr[18]
    DIRECTION INPUT ;
    USE SIGNAL ;
    ANTENNAGATEAREA 0.560700 ;
    ANTENNADIFFAREA 0.434700 ;
    PORT
      LAYER met2 ;
        RECT 231.930 446.000 232.210 450.000 ;
    END
  END rpg_st_addr[18]
  PIN rpg_st_addr[19]
    DIRECTION INPUT ;
    USE SIGNAL ;
    ANTENNAGATEAREA 0.560700 ;
    ANTENNADIFFAREA 0.434700 ;
    PORT
      LAYER met2 ;
        RECT 212.610 446.000 212.890 450.000 ;
    END
  END rpg_st_addr[19]
  PIN rpg_st_addr[1]
    DIRECTION INPUT ;
    USE SIGNAL ;
    ANTENNAGATEAREA 0.560700 ;
    ANTENNADIFFAREA 0.434700 ;
    PORT
      LAYER met2 ;
        RECT 225.490 446.000 225.770 450.000 ;
    END
  END rpg_st_addr[1]
  PIN rpg_st_addr[20]
    DIRECTION INPUT ;
    USE SIGNAL ;
    ANTENNAGATEAREA 0.560700 ;
    ANTENNADIFFAREA 0.434700 ;
    PORT
      LAYER met2 ;
        RECT 74.150 446.000 74.430 450.000 ;
    END
  END rpg_st_addr[20]
  PIN rpg_st_addr[21]
    DIRECTION INPUT ;
    USE SIGNAL ;
    ANTENNAGATEAREA 0.560700 ;
    ANTENNADIFFAREA 0.434700 ;
    PORT
      LAYER met2 ;
        RECT 12.970 446.000 13.250 450.000 ;
    END
  END rpg_st_addr[21]
  PIN rpg_st_addr[22]
    DIRECTION INPUT ;
    USE SIGNAL ;
    ANTENNAGATEAREA 0.560700 ;
    ANTENNADIFFAREA 0.434700 ;
    PORT
      LAYER met2 ;
        RECT 16.190 446.000 16.470 450.000 ;
    END
  END rpg_st_addr[22]
  PIN rpg_st_addr[23]
    DIRECTION INPUT ;
    USE SIGNAL ;
    ANTENNAGATEAREA 0.560700 ;
    ANTENNADIFFAREA 0.434700 ;
    PORT
      LAYER met2 ;
        RECT 41.950 446.000 42.230 450.000 ;
    END
  END rpg_st_addr[23]
  PIN rpg_st_addr[24]
    DIRECTION INPUT ;
    USE SIGNAL ;
    ANTENNAGATEAREA 0.560700 ;
    ANTENNADIFFAREA 0.434700 ;
    PORT
      LAYER met2 ;
        RECT 228.710 446.000 228.990 450.000 ;
    END
  END rpg_st_addr[24]
  PIN rpg_st_addr[25]
    DIRECTION INPUT ;
    USE SIGNAL ;
    ANTENNAGATEAREA 0.560700 ;
    ANTENNADIFFAREA 0.434700 ;
    PORT
      LAYER met2 ;
        RECT 161.090 446.000 161.370 450.000 ;
    END
  END rpg_st_addr[25]
  PIN rpg_st_addr[26]
    DIRECTION INPUT ;
    USE SIGNAL ;
    ANTENNAGATEAREA 0.560700 ;
    ANTENNADIFFAREA 0.434700 ;
    PORT
      LAYER met2 ;
        RECT 122.450 446.000 122.730 450.000 ;
    END
  END rpg_st_addr[26]
  PIN rpg_st_addr[27]
    DIRECTION INPUT ;
    USE SIGNAL ;
    ANTENNAGATEAREA 0.560700 ;
    ANTENNADIFFAREA 0.434700 ;
    PORT
      LAYER met2 ;
        RECT 58.050 446.000 58.330 450.000 ;
    END
  END rpg_st_addr[27]
  PIN rpg_st_addr[28]
    DIRECTION INPUT ;
    USE SIGNAL ;
    ANTENNAGATEAREA 0.560700 ;
    ANTENNADIFFAREA 0.434700 ;
    PORT
      LAYER met2 ;
        RECT 9.750 446.000 10.030 450.000 ;
    END
  END rpg_st_addr[28]
  PIN rpg_st_addr[29]
    DIRECTION INPUT ;
    USE SIGNAL ;
    ANTENNAGATEAREA 0.560700 ;
    ANTENNADIFFAREA 0.434700 ;
    PORT
      LAYER met2 ;
        RECT 90.250 446.000 90.530 450.000 ;
    END
  END rpg_st_addr[29]
  PIN rpg_st_addr[2]
    DIRECTION INPUT ;
    USE SIGNAL ;
    ANTENNAGATEAREA 0.560700 ;
    ANTENNADIFFAREA 0.434700 ;
    PORT
      LAYER met2 ;
        RECT 428.350 446.000 428.630 450.000 ;
    END
  END rpg_st_addr[2]
  PIN rpg_st_addr[30]
    DIRECTION INPUT ;
    USE SIGNAL ;
    ANTENNAGATEAREA 0.995400 ;
    ANTENNADIFFAREA 0.869400 ;
    PORT
      LAYER met2 ;
        RECT 22.630 446.000 22.910 450.000 ;
    END
  END rpg_st_addr[30]
  PIN rpg_st_addr[31]
    DIRECTION INPUT ;
    USE SIGNAL ;
    ANTENNAGATEAREA 0.560700 ;
    ANTENNADIFFAREA 0.434700 ;
    PORT
      LAYER met2 ;
        RECT 99.910 446.000 100.190 450.000 ;
    END
  END rpg_st_addr[31]
  PIN rpg_st_addr[32]
    DIRECTION INPUT ;
    USE SIGNAL ;
    ANTENNAGATEAREA 0.995400 ;
    ANTENNADIFFAREA 0.869400 ;
    PORT
      LAYER met2 ;
        RECT 418.690 446.000 418.970 450.000 ;
    END
  END rpg_st_addr[32]
  PIN rpg_st_addr[33]
    DIRECTION INPUT ;
    USE SIGNAL ;
    ANTENNAGATEAREA 0.560700 ;
    ANTENNADIFFAREA 0.434700 ;
    PORT
      LAYER met2 ;
        RECT 148.210 446.000 148.490 450.000 ;
    END
  END rpg_st_addr[33]
  PIN rpg_st_addr[34]
    DIRECTION INPUT ;
    USE SIGNAL ;
    ANTENNAGATEAREA 0.560700 ;
    ANTENNADIFFAREA 0.434700 ;
    PORT
      LAYER met2 ;
        RECT 154.650 446.000 154.930 450.000 ;
    END
  END rpg_st_addr[34]
  PIN rpg_st_addr[35]
    DIRECTION INPUT ;
    USE SIGNAL ;
    ANTENNAGATEAREA 0.560700 ;
    ANTENNADIFFAREA 0.434700 ;
    PORT
      LAYER met2 ;
        RECT 190.070 446.000 190.350 450.000 ;
    END
  END rpg_st_addr[35]
  PIN rpg_st_addr[36]
    DIRECTION INPUT ;
    USE SIGNAL ;
    ANTENNAGATEAREA 0.560700 ;
    ANTENNADIFFAREA 0.434700 ;
    PORT
      LAYER met2 ;
        RECT 77.370 446.000 77.650 450.000 ;
    END
  END rpg_st_addr[36]
  PIN rpg_st_addr[37]
    DIRECTION INPUT ;
    USE SIGNAL ;
    ANTENNAGATEAREA 0.995400 ;
    ANTENNADIFFAREA 0.869400 ;
    PORT
      LAYER met2 ;
        RECT 67.710 446.000 67.990 450.000 ;
    END
  END rpg_st_addr[37]
  PIN rpg_st_addr[38]
    DIRECTION INPUT ;
    USE SIGNAL ;
    ANTENNAGATEAREA 0.995400 ;
    ANTENNADIFFAREA 0.869400 ;
    PORT
      LAYER met2 ;
        RECT 29.070 446.000 29.350 450.000 ;
    END
  END rpg_st_addr[38]
  PIN rpg_st_addr[39]
    DIRECTION INPUT ;
    USE SIGNAL ;
    ANTENNAGATEAREA 0.995400 ;
    ANTENNADIFFAREA 0.869400 ;
    PORT
      LAYER met2 ;
        RECT 25.850 446.000 26.130 450.000 ;
    END
  END rpg_st_addr[39]
  PIN rpg_st_addr[3]
    DIRECTION INPUT ;
    USE SIGNAL ;
    ANTENNAGATEAREA 0.560700 ;
    ANTENNADIFFAREA 0.434700 ;
    PORT
      LAYER met2 ;
        RECT 338.190 446.000 338.470 450.000 ;
    END
  END rpg_st_addr[3]
  PIN rpg_st_addr[40]
    DIRECTION INPUT ;
    USE SIGNAL ;
    ANTENNAGATEAREA 0.560700 ;
    ANTENNADIFFAREA 0.434700 ;
    PORT
      LAYER met3 ;
        RECT 0.000 343.440 4.000 344.040 ;
    END
  END rpg_st_addr[40]
  PIN rpg_st_addr[41]
    DIRECTION INPUT ;
    USE SIGNAL ;
    ANTENNAGATEAREA 0.560700 ;
    ANTENNADIFFAREA 0.434700 ;
    PORT
      LAYER met3 ;
        RECT 0.000 329.840 4.000 330.440 ;
    END
  END rpg_st_addr[41]
  PIN rpg_st_addr[42]
    DIRECTION INPUT ;
    USE SIGNAL ;
    ANTENNAGATEAREA 0.560700 ;
    ANTENNADIFFAREA 0.434700 ;
    PORT
      LAYER met3 ;
        RECT 0.000 333.240 4.000 333.840 ;
    END
  END rpg_st_addr[42]
  PIN rpg_st_addr[43]
    DIRECTION INPUT ;
    USE SIGNAL ;
    ANTENNAGATEAREA 0.560700 ;
    ANTENNADIFFAREA 0.434700 ;
    PORT
      LAYER met3 ;
        RECT 0.000 340.040 4.000 340.640 ;
    END
  END rpg_st_addr[43]
  PIN rpg_st_addr[44]
    DIRECTION INPUT ;
    USE SIGNAL ;
    ANTENNAGATEAREA 0.560700 ;
    ANTENNADIFFAREA 0.434700 ;
    PORT
      LAYER met3 ;
        RECT 0.000 425.040 4.000 425.640 ;
    END
  END rpg_st_addr[44]
  PIN rpg_st_addr[45]
    DIRECTION INPUT ;
    USE SIGNAL ;
    ANTENNAGATEAREA 0.560700 ;
    ANTENNADIFFAREA 0.434700 ;
    PORT
      LAYER met3 ;
        RECT 0.000 384.240 4.000 384.840 ;
    END
  END rpg_st_addr[45]
  PIN rpg_st_addr[46]
    DIRECTION INPUT ;
    USE SIGNAL ;
    ANTENNAGATEAREA 0.995400 ;
    ANTENNADIFFAREA 0.869400 ;
    PORT
      LAYER met3 ;
        RECT 0.000 421.640 4.000 422.240 ;
    END
  END rpg_st_addr[46]
  PIN rpg_st_addr[47]
    DIRECTION INPUT ;
    USE SIGNAL ;
    ANTENNAGATEAREA 0.995400 ;
    ANTENNADIFFAREA 0.869400 ;
    PORT
      LAYER met3 ;
        RECT 0.000 418.240 4.000 418.840 ;
    END
  END rpg_st_addr[47]
  PIN rpg_st_addr[48]
    DIRECTION INPUT ;
    USE SIGNAL ;
    ANTENNAGATEAREA 0.560700 ;
    ANTENNADIFFAREA 0.434700 ;
    PORT
      LAYER met3 ;
        RECT 0.000 414.840 4.000 415.440 ;
    END
  END rpg_st_addr[48]
  PIN rpg_st_addr[49]
    DIRECTION INPUT ;
    USE SIGNAL ;
    ANTENNAGATEAREA 0.560700 ;
    ANTENNADIFFAREA 0.434700 ;
    PORT
      LAYER met3 ;
        RECT 0.000 408.040 4.000 408.640 ;
    END
  END rpg_st_addr[49]
  PIN rpg_st_addr[4]
    DIRECTION INPUT ;
    USE SIGNAL ;
    ANTENNAGATEAREA 0.560700 ;
    ANTENNADIFFAREA 0.434700 ;
    PORT
      LAYER met3 ;
        RECT 0.000 336.640 4.000 337.240 ;
    END
  END rpg_st_addr[4]
  PIN rpg_st_addr[50]
    DIRECTION INPUT ;
    USE SIGNAL ;
    ANTENNAGATEAREA 0.560700 ;
    ANTENNADIFFAREA 0.434700 ;
    PORT
      LAYER met3 ;
        RECT 0.000 411.440 4.000 412.040 ;
    END
  END rpg_st_addr[50]
  PIN rpg_st_addr[51]
    DIRECTION INPUT ;
    USE SIGNAL ;
    ANTENNAGATEAREA 0.560700 ;
    ANTENNADIFFAREA 0.434700 ;
    PORT
      LAYER met3 ;
        RECT 0.000 309.440 4.000 310.040 ;
    END
  END rpg_st_addr[51]
  PIN rpg_st_addr[52]
    DIRECTION INPUT ;
    USE SIGNAL ;
    ANTENNAGATEAREA 0.560700 ;
    ANTENNADIFFAREA 0.434700 ;
    PORT
      LAYER met3 ;
        RECT 0.000 302.640 4.000 303.240 ;
    END
  END rpg_st_addr[52]
  PIN rpg_st_addr[53]
    DIRECTION INPUT ;
    USE SIGNAL ;
    ANTENNAGATEAREA 0.560700 ;
    ANTENNADIFFAREA 0.434700 ;
    PORT
      LAYER met3 ;
        RECT 0.000 316.240 4.000 316.840 ;
    END
  END rpg_st_addr[53]
  PIN rpg_st_addr[54]
    DIRECTION INPUT ;
    USE SIGNAL ;
    ANTENNAGATEAREA 0.560700 ;
    ANTENNADIFFAREA 0.434700 ;
    PORT
      LAYER met3 ;
        RECT 0.000 323.040 4.000 323.640 ;
    END
  END rpg_st_addr[54]
  PIN rpg_st_addr[55]
    DIRECTION INPUT ;
    USE SIGNAL ;
    ANTENNAGATEAREA 0.560700 ;
    ANTENNADIFFAREA 0.434700 ;
    PORT
      LAYER met3 ;
        RECT 0.000 326.440 4.000 327.040 ;
    END
  END rpg_st_addr[55]
  PIN rpg_st_addr[56]
    DIRECTION INPUT ;
    USE SIGNAL ;
    ANTENNAGATEAREA 0.560700 ;
    ANTENNADIFFAREA 0.434700 ;
    PORT
      LAYER met3 ;
        RECT 0.000 367.240 4.000 367.840 ;
    END
  END rpg_st_addr[56]
  PIN rpg_st_addr[57]
    DIRECTION INPUT ;
    USE SIGNAL ;
    ANTENNAGATEAREA 0.560700 ;
    ANTENNADIFFAREA 0.434700 ;
    PORT
      LAYER met3 ;
        RECT 0.000 346.840 4.000 347.440 ;
    END
  END rpg_st_addr[57]
  PIN rpg_st_addr[58]
    DIRECTION INPUT ;
    USE SIGNAL ;
    ANTENNAGATEAREA 0.560700 ;
    ANTENNADIFFAREA 0.434700 ;
    PORT
      LAYER met3 ;
        RECT 0.000 387.640 4.000 388.240 ;
    END
  END rpg_st_addr[58]
  PIN rpg_st_addr[59]
    DIRECTION INPUT ;
    USE SIGNAL ;
    ANTENNAGATEAREA 0.560700 ;
    ANTENNADIFFAREA 0.434700 ;
    PORT
      LAYER met3 ;
        RECT 0.000 357.040 4.000 357.640 ;
    END
  END rpg_st_addr[59]
  PIN rpg_st_addr[5]
    DIRECTION INPUT ;
    USE SIGNAL ;
    ANTENNAGATEAREA 0.560700 ;
    ANTENNADIFFAREA 0.434700 ;
    PORT
      LAYER met3 ;
        RECT 0.000 350.240 4.000 350.840 ;
    END
  END rpg_st_addr[5]
  PIN rpg_st_addr[60]
    DIRECTION INPUT ;
    USE SIGNAL ;
    ANTENNAGATEAREA 0.560700 ;
    ANTENNADIFFAREA 0.434700 ;
    PORT
      LAYER met3 ;
        RECT 0.000 363.840 4.000 364.440 ;
    END
  END rpg_st_addr[60]
  PIN rpg_st_addr[61]
    DIRECTION INPUT ;
    USE SIGNAL ;
    ANTENNAGATEAREA 0.560700 ;
    ANTENNADIFFAREA 0.434700 ;
    PORT
      LAYER met3 ;
        RECT 0.000 377.440 4.000 378.040 ;
    END
  END rpg_st_addr[61]
  PIN rpg_st_addr[62]
    DIRECTION INPUT ;
    USE SIGNAL ;
    ANTENNAGATEAREA 0.560700 ;
    ANTENNADIFFAREA 0.434700 ;
    PORT
      LAYER met3 ;
        RECT 0.000 380.840 4.000 381.440 ;
    END
  END rpg_st_addr[62]
  PIN rpg_st_addr[63]
    DIRECTION INPUT ;
    USE SIGNAL ;
    ANTENNAGATEAREA 0.560700 ;
    ANTENNADIFFAREA 0.434700 ;
    PORT
      LAYER met3 ;
        RECT 0.000 404.640 4.000 405.240 ;
    END
  END rpg_st_addr[63]
  PIN rpg_st_addr[64]
    DIRECTION INPUT ;
    USE SIGNAL ;
    ANTENNAGATEAREA 0.560700 ;
    ANTENNADIFFAREA 0.434700 ;
    PORT
      LAYER met3 ;
        RECT 0.000 394.440 4.000 395.040 ;
    END
  END rpg_st_addr[64]
  PIN rpg_st_addr[65]
    DIRECTION INPUT ;
    USE SIGNAL ;
    ANTENNAGATEAREA 0.560700 ;
    ANTENNADIFFAREA 0.434700 ;
    PORT
      LAYER met3 ;
        RECT 0.000 391.040 4.000 391.640 ;
    END
  END rpg_st_addr[65]
  PIN rpg_st_addr[66]
    DIRECTION INPUT ;
    USE SIGNAL ;
    ANTENNAGATEAREA 0.560700 ;
    ANTENNADIFFAREA 0.434700 ;
    PORT
      LAYER met3 ;
        RECT 0.000 397.840 4.000 398.440 ;
    END
  END rpg_st_addr[66]
  PIN rpg_st_addr[67]
    DIRECTION INPUT ;
    USE SIGNAL ;
    ANTENNAGATEAREA 0.560700 ;
    ANTENNADIFFAREA 0.434700 ;
    PORT
      LAYER met3 ;
        RECT 0.000 401.240 4.000 401.840 ;
    END
  END rpg_st_addr[67]
  PIN rpg_st_addr[6]
    DIRECTION INPUT ;
    USE SIGNAL ;
    ANTENNAGATEAREA 0.560700 ;
    ANTENNADIFFAREA 0.434700 ;
    PORT
      LAYER met3 ;
        RECT 0.000 353.640 4.000 354.240 ;
    END
  END rpg_st_addr[6]
  PIN rpg_st_addr[7]
    DIRECTION INPUT ;
    USE SIGNAL ;
    ANTENNAGATEAREA 0.560700 ;
    ANTENNADIFFAREA 0.434700 ;
    PORT
      LAYER met3 ;
        RECT 0.000 370.640 4.000 371.240 ;
    END
  END rpg_st_addr[7]
  PIN rpg_st_addr[8]
    DIRECTION INPUT ;
    USE SIGNAL ;
    ANTENNAGATEAREA 0.560700 ;
    ANTENNADIFFAREA 0.434700 ;
    PORT
      LAYER met3 ;
        RECT 0.000 360.440 4.000 361.040 ;
    END
  END rpg_st_addr[8]
  PIN rpg_st_addr[9]
    DIRECTION INPUT ;
    USE SIGNAL ;
    ANTENNAGATEAREA 0.560700 ;
    ANTENNADIFFAREA 0.434700 ;
    PORT
      LAYER met3 ;
        RECT 0.000 374.040 4.000 374.640 ;
    END
  END rpg_st_addr[9]
  PIN vccd1
    DIRECTION INOUT ;
    USE POWER ;
    PORT
      LAYER met4 ;
        RECT 21.040 10.640 22.640 438.160 ;
    END
    PORT
      LAYER met4 ;
        RECT 174.640 10.640 176.240 438.160 ;
    END
    PORT
      LAYER met4 ;
        RECT 328.240 10.640 329.840 438.160 ;
    END
  END vccd1
  PIN vssd1
    DIRECTION INOUT ;
    USE GROUND ;
    PORT
      LAYER met4 ;
        RECT 24.340 10.640 25.940 438.160 ;
    END
    PORT
      LAYER met4 ;
        RECT 177.940 10.640 179.540 438.160 ;
    END
    PORT
      LAYER met4 ;
        RECT 331.540 10.640 333.140 438.160 ;
    END
  END vssd1
  PIN wpg_ack[0]
    DIRECTION OUTPUT ;
    USE SIGNAL ;
    ANTENNADIFFAREA 0.340600 ;
    PORT
      LAYER met3 ;
        RECT 446.000 139.440 450.000 140.040 ;
    END
  END wpg_ack[0]
  PIN wpg_ack[1]
    DIRECTION OUTPUT ;
    USE SIGNAL ;
    ANTENNADIFFAREA 0.340600 ;
    PORT
      LAYER met3 ;
        RECT 446.000 261.840 450.000 262.440 ;
    END
  END wpg_ack[1]
  PIN wpg_ack[2]
    DIRECTION OUTPUT ;
    USE SIGNAL ;
    ANTENNADIFFAREA 0.340600 ;
    PORT
      LAYER met3 ;
        RECT 446.000 30.640 450.000 31.240 ;
    END
  END wpg_ack[2]
  PIN wpg_burst_length[0]
    DIRECTION INPUT ;
    USE SIGNAL ;
    ANTENNAGATEAREA 0.560700 ;
    ANTENNADIFFAREA 0.434700 ;
    PORT
      LAYER met3 ;
        RECT 446.000 295.840 450.000 296.440 ;
    END
  END wpg_burst_length[0]
  PIN wpg_burst_length[10]
    DIRECTION INPUT ;
    USE SIGNAL ;
    ANTENNAGATEAREA 0.560700 ;
    ANTENNADIFFAREA 0.434700 ;
    PORT
      LAYER met3 ;
        RECT 446.000 136.040 450.000 136.640 ;
    END
  END wpg_burst_length[10]
  PIN wpg_burst_length[11]
    DIRECTION INPUT ;
    USE SIGNAL ;
    ANTENNAGATEAREA 0.560700 ;
    ANTENNADIFFAREA 0.434700 ;
    PORT
      LAYER met3 ;
        RECT 446.000 146.240 450.000 146.840 ;
    END
  END wpg_burst_length[11]
  PIN wpg_burst_length[12]
    DIRECTION INPUT ;
    USE SIGNAL ;
    ANTENNAGATEAREA 0.560700 ;
    ANTENNADIFFAREA 0.434700 ;
    PORT
      LAYER met3 ;
        RECT 446.000 129.240 450.000 129.840 ;
    END
  END wpg_burst_length[12]
  PIN wpg_burst_length[13]
    DIRECTION INPUT ;
    USE SIGNAL ;
    ANTENNAGATEAREA 0.560700 ;
    ANTENNADIFFAREA 0.434700 ;
    PORT
      LAYER met3 ;
        RECT 446.000 224.440 450.000 225.040 ;
    END
  END wpg_burst_length[13]
  PIN wpg_burst_length[14]
    DIRECTION INPUT ;
    USE SIGNAL ;
    ANTENNAGATEAREA 0.560700 ;
    ANTENNADIFFAREA 0.434700 ;
    PORT
      LAYER met3 ;
        RECT 446.000 207.440 450.000 208.040 ;
    END
  END wpg_burst_length[14]
  PIN wpg_burst_length[15]
    DIRECTION INPUT ;
    USE SIGNAL ;
    ANTENNAGATEAREA 0.560700 ;
    ANTENNADIFFAREA 0.434700 ;
    PORT
      LAYER met3 ;
        RECT 446.000 272.040 450.000 272.640 ;
    END
  END wpg_burst_length[15]
  PIN wpg_burst_length[16]
    DIRECTION INPUT ;
    USE SIGNAL ;
    ANTENNAGATEAREA 0.560700 ;
    ANTENNADIFFAREA 0.434700 ;
    PORT
      LAYER met3 ;
        RECT 446.000 302.640 450.000 303.240 ;
    END
  END wpg_burst_length[16]
  PIN wpg_burst_length[17]
    DIRECTION INPUT ;
    USE SIGNAL ;
    ANTENNAGATEAREA 0.560700 ;
    ANTENNADIFFAREA 0.434700 ;
    PORT
      LAYER met3 ;
        RECT 446.000 333.240 450.000 333.840 ;
    END
  END wpg_burst_length[17]
  PIN wpg_burst_length[18]
    DIRECTION INPUT ;
    USE SIGNAL ;
    ANTENNAGATEAREA 0.560700 ;
    ANTENNADIFFAREA 0.434700 ;
    PORT
      LAYER met3 ;
        RECT 446.000 343.440 450.000 344.040 ;
    END
  END wpg_burst_length[18]
  PIN wpg_burst_length[19]
    DIRECTION INPUT ;
    USE SIGNAL ;
    ANTENNAGATEAREA 0.560700 ;
    ANTENNADIFFAREA 0.434700 ;
    PORT
      LAYER met3 ;
        RECT 446.000 350.240 450.000 350.840 ;
    END
  END wpg_burst_length[19]
  PIN wpg_burst_length[1]
    DIRECTION INPUT ;
    USE SIGNAL ;
    ANTENNAGATEAREA 0.560700 ;
    ANTENNADIFFAREA 0.434700 ;
    PORT
      LAYER met3 ;
        RECT 446.000 299.240 450.000 299.840 ;
    END
  END wpg_burst_length[1]
  PIN wpg_burst_length[20]
    DIRECTION INPUT ;
    USE SIGNAL ;
    ANTENNAGATEAREA 0.560700 ;
    ANTENNADIFFAREA 0.434700 ;
    PORT
      LAYER met3 ;
        RECT 446.000 346.840 450.000 347.440 ;
    END
  END wpg_burst_length[20]
  PIN wpg_burst_length[21]
    DIRECTION INPUT ;
    USE SIGNAL ;
    ANTENNAGATEAREA 0.560700 ;
    ANTENNADIFFAREA 0.434700 ;
    PORT
      LAYER met3 ;
        RECT 446.000 326.440 450.000 327.040 ;
    END
  END wpg_burst_length[21]
  PIN wpg_burst_length[22]
    DIRECTION INPUT ;
    USE SIGNAL ;
    ANTENNAGATEAREA 0.560700 ;
    ANTENNADIFFAREA 0.434700 ;
    PORT
      LAYER met3 ;
        RECT 446.000 340.040 450.000 340.640 ;
    END
  END wpg_burst_length[22]
  PIN wpg_burst_length[23]
    DIRECTION INPUT ;
    USE SIGNAL ;
    ANTENNAGATEAREA 0.560700 ;
    ANTENNADIFFAREA 0.434700 ;
    PORT
      LAYER met3 ;
        RECT 446.000 265.240 450.000 265.840 ;
    END
  END wpg_burst_length[23]
  PIN wpg_burst_length[24]
    DIRECTION INPUT ;
    USE SIGNAL ;
    ANTENNAGATEAREA 0.560700 ;
    ANTENNADIFFAREA 0.434700 ;
    PORT
      LAYER met3 ;
        RECT 446.000 234.640 450.000 235.240 ;
    END
  END wpg_burst_length[24]
  PIN wpg_burst_length[25]
    DIRECTION INPUT ;
    USE SIGNAL ;
    ANTENNAGATEAREA 0.560700 ;
    ANTENNADIFFAREA 0.434700 ;
    PORT
      LAYER met3 ;
        RECT 446.000 285.640 450.000 286.240 ;
    END
  END wpg_burst_length[25]
  PIN wpg_burst_length[26]
    DIRECTION INPUT ;
    USE SIGNAL ;
    ANTENNAGATEAREA 0.560700 ;
    ANTENNADIFFAREA 0.434700 ;
    PORT
      LAYER met3 ;
        RECT 446.000 309.440 450.000 310.040 ;
    END
  END wpg_burst_length[26]
  PIN wpg_burst_length[27]
    DIRECTION INPUT ;
    USE SIGNAL ;
    ANTENNAGATEAREA 0.560700 ;
    ANTENNADIFFAREA 0.434700 ;
    PORT
      LAYER met3 ;
        RECT 446.000 316.240 450.000 316.840 ;
    END
  END wpg_burst_length[27]
  PIN wpg_burst_length[28]
    DIRECTION INPUT ;
    USE SIGNAL ;
    ANTENNAGATEAREA 0.560700 ;
    ANTENNADIFFAREA 0.434700 ;
    PORT
      LAYER met3 ;
        RECT 446.000 319.640 450.000 320.240 ;
    END
  END wpg_burst_length[28]
  PIN wpg_burst_length[29]
    DIRECTION INPUT ;
    USE SIGNAL ;
    ANTENNAGATEAREA 0.560700 ;
    ANTENNADIFFAREA 0.434700 ;
    PORT
      LAYER met3 ;
        RECT 446.000 275.440 450.000 276.040 ;
    END
  END wpg_burst_length[29]
  PIN wpg_burst_length[2]
    DIRECTION INPUT ;
    USE SIGNAL ;
    ANTENNAGATEAREA 0.560700 ;
    ANTENNADIFFAREA 0.434700 ;
    PORT
      LAYER met3 ;
        RECT 446.000 244.840 450.000 245.440 ;
    END
  END wpg_burst_length[2]
  PIN wpg_burst_length[30]
    DIRECTION INPUT ;
    USE SIGNAL ;
    ANTENNAGATEAREA 0.560700 ;
    ANTENNADIFFAREA 0.434700 ;
    PORT
      LAYER met3 ;
        RECT 446.000 312.840 450.000 313.440 ;
    END
  END wpg_burst_length[30]
  PIN wpg_burst_length[31]
    DIRECTION INPUT ;
    USE SIGNAL ;
    ANTENNAGATEAREA 0.560700 ;
    ANTENNADIFFAREA 0.434700 ;
    PORT
      LAYER met3 ;
        RECT 446.000 306.040 450.000 306.640 ;
    END
  END wpg_burst_length[31]
  PIN wpg_burst_length[32]
    DIRECTION INPUT ;
    USE SIGNAL ;
    ANTENNAGATEAREA 0.560700 ;
    ANTENNADIFFAREA 0.434700 ;
    PORT
      LAYER met3 ;
        RECT 446.000 323.040 450.000 323.640 ;
    END
  END wpg_burst_length[32]
  PIN wpg_burst_length[33]
    DIRECTION INPUT ;
    USE SIGNAL ;
    ANTENNAGATEAREA 0.560700 ;
    ANTENNADIFFAREA 0.434700 ;
    PORT
      LAYER met3 ;
        RECT 446.000 329.840 450.000 330.440 ;
    END
  END wpg_burst_length[33]
  PIN wpg_burst_length[34]
    DIRECTION INPUT ;
    USE SIGNAL ;
    ANTENNAGATEAREA 0.560700 ;
    ANTENNADIFFAREA 0.434700 ;
    PORT
      LAYER met3 ;
        RECT 446.000 13.640 450.000 14.240 ;
    END
  END wpg_burst_length[34]
  PIN wpg_burst_length[35]
    DIRECTION INPUT ;
    USE SIGNAL ;
    ANTENNAGATEAREA 0.560700 ;
    ANTENNADIFFAREA 0.434700 ;
    PORT
      LAYER met3 ;
        RECT 446.000 3.440 450.000 4.040 ;
    END
  END wpg_burst_length[35]
  PIN wpg_burst_length[36]
    DIRECTION INPUT ;
    USE SIGNAL ;
    ANTENNAGATEAREA 0.560700 ;
    ANTENNADIFFAREA 0.434700 ;
    PORT
      LAYER met3 ;
        RECT 446.000 408.040 450.000 408.640 ;
    END
  END wpg_burst_length[36]
  PIN wpg_burst_length[37]
    DIRECTION INPUT ;
    USE SIGNAL ;
    ANTENNAGATEAREA 0.560700 ;
    ANTENNADIFFAREA 0.434700 ;
    PORT
      LAYER met3 ;
        RECT 446.000 404.640 450.000 405.240 ;
    END
  END wpg_burst_length[37]
  PIN wpg_burst_length[38]
    DIRECTION INPUT ;
    USE SIGNAL ;
    ANTENNAGATEAREA 0.560700 ;
    ANTENNADIFFAREA 0.434700 ;
    PORT
      LAYER met3 ;
        RECT 446.000 391.040 450.000 391.640 ;
    END
  END wpg_burst_length[38]
  PIN wpg_burst_length[39]
    DIRECTION INPUT ;
    USE SIGNAL ;
    ANTENNAGATEAREA 0.560700 ;
    ANTENNADIFFAREA 0.434700 ;
    PORT
      LAYER met3 ;
        RECT 446.000 122.440 450.000 123.040 ;
    END
  END wpg_burst_length[39]
  PIN wpg_burst_length[3]
    DIRECTION INPUT ;
    USE SIGNAL ;
    ANTENNAGATEAREA 0.560700 ;
    ANTENNADIFFAREA 0.434700 ;
    PORT
      LAYER met3 ;
        RECT 446.000 282.240 450.000 282.840 ;
    END
  END wpg_burst_length[3]
  PIN wpg_burst_length[40]
    DIRECTION INPUT ;
    USE SIGNAL ;
    ANTENNAGATEAREA 0.995400 ;
    ANTENNADIFFAREA 0.869400 ;
    PORT
      LAYER met3 ;
        RECT 446.000 421.640 450.000 422.240 ;
    END
  END wpg_burst_length[40]
  PIN wpg_burst_length[41]
    DIRECTION INPUT ;
    USE SIGNAL ;
    ANTENNAGATEAREA 0.560700 ;
    ANTENNADIFFAREA 0.434700 ;
    PORT
      LAYER met3 ;
        RECT 446.000 51.040 450.000 51.640 ;
    END
  END wpg_burst_length[41]
  PIN wpg_burst_length[42]
    DIRECTION INPUT ;
    USE SIGNAL ;
    ANTENNAGATEAREA 0.560700 ;
    ANTENNADIFFAREA 0.434700 ;
    PORT
      LAYER met3 ;
        RECT 446.000 85.040 450.000 85.640 ;
    END
  END wpg_burst_length[42]
  PIN wpg_burst_length[43]
    DIRECTION INPUT ;
    USE SIGNAL ;
    ANTENNAGATEAREA 0.560700 ;
    ANTENNADIFFAREA 0.434700 ;
    PORT
      LAYER met3 ;
        RECT 446.000 17.040 450.000 17.640 ;
    END
  END wpg_burst_length[43]
  PIN wpg_burst_length[44]
    DIRECTION INPUT ;
    USE SIGNAL ;
    ANTENNAGATEAREA 0.560700 ;
    ANTENNADIFFAREA 0.434700 ;
    PORT
      LAYER met3 ;
        RECT 446.000 6.840 450.000 7.440 ;
    END
  END wpg_burst_length[44]
  PIN wpg_burst_length[45]
    DIRECTION INPUT ;
    USE SIGNAL ;
    ANTENNAGATEAREA 0.560700 ;
    ANTENNADIFFAREA 0.434700 ;
    PORT
      LAYER met3 ;
        RECT 446.000 91.840 450.000 92.440 ;
    END
  END wpg_burst_length[45]
  PIN wpg_burst_length[46]
    DIRECTION INPUT ;
    USE SIGNAL ;
    ANTENNAGATEAREA 0.560700 ;
    ANTENNADIFFAREA 0.434700 ;
    PORT
      LAYER met3 ;
        RECT 446.000 61.240 450.000 61.840 ;
    END
  END wpg_burst_length[46]
  PIN wpg_burst_length[47]
    DIRECTION INPUT ;
    USE SIGNAL ;
    ANTENNAGATEAREA 0.560700 ;
    ANTENNADIFFAREA 0.434700 ;
    PORT
      LAYER met3 ;
        RECT 446.000 102.040 450.000 102.640 ;
    END
  END wpg_burst_length[47]
  PIN wpg_burst_length[48]
    DIRECTION INPUT ;
    USE SIGNAL ;
    ANTENNAGATEAREA 0.560700 ;
    ANTENNADIFFAREA 0.434700 ;
    PORT
      LAYER met3 ;
        RECT 446.000 105.440 450.000 106.040 ;
    END
  END wpg_burst_length[48]
  PIN wpg_burst_length[49]
    DIRECTION INPUT ;
    USE SIGNAL ;
    ANTENNAGATEAREA 0.560700 ;
    ANTENNADIFFAREA 0.434700 ;
    PORT
      LAYER met3 ;
        RECT 446.000 54.440 450.000 55.040 ;
    END
  END wpg_burst_length[49]
  PIN wpg_burst_length[4]
    DIRECTION INPUT ;
    USE SIGNAL ;
    ANTENNAGATEAREA 0.560700 ;
    ANTENNADIFFAREA 0.434700 ;
    PORT
      LAYER met3 ;
        RECT 446.000 278.840 450.000 279.440 ;
    END
  END wpg_burst_length[4]
  PIN wpg_burst_length[50]
    DIRECTION INPUT ;
    USE SIGNAL ;
    ANTENNAGATEAREA 0.560700 ;
    ANTENNADIFFAREA 0.434700 ;
    PORT
      LAYER met3 ;
        RECT 446.000 68.040 450.000 68.640 ;
    END
  END wpg_burst_length[50]
  PIN wpg_burst_length[5]
    DIRECTION INPUT ;
    USE SIGNAL ;
    ANTENNAGATEAREA 0.560700 ;
    ANTENNADIFFAREA 0.434700 ;
    PORT
      LAYER met3 ;
        RECT 446.000 251.640 450.000 252.240 ;
    END
  END wpg_burst_length[5]
  PIN wpg_burst_length[6]
    DIRECTION INPUT ;
    USE SIGNAL ;
    ANTENNAGATEAREA 0.560700 ;
    ANTENNADIFFAREA 0.434700 ;
    PORT
      LAYER met3 ;
        RECT 446.000 268.640 450.000 269.240 ;
    END
  END wpg_burst_length[6]
  PIN wpg_burst_length[7]
    DIRECTION INPUT ;
    USE SIGNAL ;
    ANTENNAGATEAREA 0.560700 ;
    ANTENNADIFFAREA 0.434700 ;
    PORT
      LAYER met3 ;
        RECT 446.000 231.240 450.000 231.840 ;
    END
  END wpg_burst_length[7]
  PIN wpg_burst_length[8]
    DIRECTION INPUT ;
    USE SIGNAL ;
    ANTENNAGATEAREA 0.560700 ;
    ANTENNADIFFAREA 0.434700 ;
    PORT
      LAYER met3 ;
        RECT 446.000 238.040 450.000 238.640 ;
    END
  END wpg_burst_length[8]
  PIN wpg_burst_length[9]
    DIRECTION INPUT ;
    USE SIGNAL ;
    ANTENNAGATEAREA 0.560700 ;
    ANTENNADIFFAREA 0.434700 ;
    PORT
      LAYER met3 ;
        RECT 446.000 159.840 450.000 160.440 ;
    END
  END wpg_burst_length[9]
  PIN wpg_busy[0]
    DIRECTION INPUT ;
    USE SIGNAL ;
    ANTENNAGATEAREA 0.560700 ;
    ANTENNADIFFAREA 0.434700 ;
    PORT
      LAYER met3 ;
        RECT 446.000 156.440 450.000 157.040 ;
    END
  END wpg_busy[0]
  PIN wpg_busy[1]
    DIRECTION INPUT ;
    USE SIGNAL ;
    ANTENNAGATEAREA 0.560700 ;
    ANTENNADIFFAREA 0.434700 ;
    PORT
      LAYER met3 ;
        RECT 446.000 292.440 450.000 293.040 ;
    END
  END wpg_busy[1]
  PIN wpg_busy[2]
    DIRECTION INPUT ;
    USE SIGNAL ;
    ANTENNAGATEAREA 0.560700 ;
    ANTENNADIFFAREA 0.434700 ;
    PORT
      LAYER met3 ;
        RECT 446.000 78.240 450.000 78.840 ;
    END
  END wpg_busy[2]
  PIN wpg_st_addr[0]
    DIRECTION INPUT ;
    USE SIGNAL ;
    ANTENNAGATEAREA 0.560700 ;
    ANTENNADIFFAREA 0.434700 ;
    PORT
      LAYER met3 ;
        RECT 446.000 23.840 450.000 24.440 ;
    END
  END wpg_st_addr[0]
  PIN wpg_st_addr[10]
    DIRECTION INPUT ;
    USE SIGNAL ;
    ANTENNAGATEAREA 0.560700 ;
    ANTENNADIFFAREA 0.434700 ;
    PORT
      LAYER met3 ;
        RECT 446.000 374.040 450.000 374.640 ;
    END
  END wpg_st_addr[10]
  PIN wpg_st_addr[11]
    DIRECTION INPUT ;
    USE SIGNAL ;
    ANTENNAGATEAREA 0.560700 ;
    ANTENNADIFFAREA 0.434700 ;
    PORT
      LAYER met3 ;
        RECT 446.000 387.640 450.000 388.240 ;
    END
  END wpg_st_addr[11]
  PIN wpg_st_addr[12]
    DIRECTION INPUT ;
    USE SIGNAL ;
    ANTENNAGATEAREA 0.560700 ;
    ANTENNADIFFAREA 0.434700 ;
    PORT
      LAYER met3 ;
        RECT 446.000 397.840 450.000 398.440 ;
    END
  END wpg_st_addr[12]
  PIN wpg_st_addr[13]
    DIRECTION INPUT ;
    USE SIGNAL ;
    ANTENNAGATEAREA 0.560700 ;
    ANTENNADIFFAREA 0.434700 ;
    PORT
      LAYER met3 ;
        RECT 446.000 438.640 450.000 439.240 ;
    END
  END wpg_st_addr[13]
  PIN wpg_st_addr[14]
    DIRECTION INPUT ;
    USE SIGNAL ;
    ANTENNAGATEAREA 0.560700 ;
    ANTENNADIFFAREA 0.434700 ;
    PORT
      LAYER met3 ;
        RECT 446.000 414.840 450.000 415.440 ;
    END
  END wpg_st_addr[14]
  PIN wpg_st_addr[15]
    DIRECTION INPUT ;
    USE SIGNAL ;
    ANTENNAGATEAREA 0.560700 ;
    ANTENNADIFFAREA 0.434700 ;
    PORT
      LAYER met3 ;
        RECT 446.000 431.840 450.000 432.440 ;
    END
  END wpg_st_addr[15]
  PIN wpg_st_addr[16]
    DIRECTION INPUT ;
    USE SIGNAL ;
    ANTENNAGATEAREA 0.560700 ;
    ANTENNADIFFAREA 0.434700 ;
    PORT
      LAYER met3 ;
        RECT 446.000 428.440 450.000 429.040 ;
    END
  END wpg_st_addr[16]
  PIN wpg_st_addr[17]
    DIRECTION INPUT ;
    USE SIGNAL ;
    ANTENNAGATEAREA 0.560700 ;
    ANTENNADIFFAREA 0.434700 ;
    PORT
      LAYER met3 ;
        RECT 446.000 336.640 450.000 337.240 ;
    END
  END wpg_st_addr[17]
  PIN wpg_st_addr[18]
    DIRECTION INPUT ;
    USE SIGNAL ;
    ANTENNAGATEAREA 0.560700 ;
    ANTENNADIFFAREA 0.434700 ;
    PORT
      LAYER met3 ;
        RECT 446.000 248.240 450.000 248.840 ;
    END
  END wpg_st_addr[18]
  PIN wpg_st_addr[19]
    DIRECTION INPUT ;
    USE SIGNAL ;
    ANTENNAGATEAREA 0.560700 ;
    ANTENNADIFFAREA 0.434700 ;
    PORT
      LAYER met3 ;
        RECT 446.000 241.440 450.000 242.040 ;
    END
  END wpg_st_addr[19]
  PIN wpg_st_addr[1]
    DIRECTION INPUT ;
    USE SIGNAL ;
    ANTENNAGATEAREA 0.560700 ;
    ANTENNADIFFAREA 0.434700 ;
    PORT
      LAYER met3 ;
        RECT 446.000 149.640 450.000 150.240 ;
    END
  END wpg_st_addr[1]
  PIN wpg_st_addr[20]
    DIRECTION INPUT ;
    USE SIGNAL ;
    ANTENNAGATEAREA 0.560700 ;
    ANTENNADIFFAREA 0.434700 ;
    PORT
      LAYER met3 ;
        RECT 446.000 193.840 450.000 194.440 ;
    END
  END wpg_st_addr[20]
  PIN wpg_st_addr[21]
    DIRECTION INPUT ;
    USE SIGNAL ;
    ANTENNAGATEAREA 0.560700 ;
    ANTENNADIFFAREA 0.434700 ;
    PORT
      LAYER met3 ;
        RECT 446.000 353.640 450.000 354.240 ;
    END
  END wpg_st_addr[21]
  PIN wpg_st_addr[22]
    DIRECTION INPUT ;
    USE SIGNAL ;
    ANTENNAGATEAREA 0.560700 ;
    ANTENNADIFFAREA 0.434700 ;
    PORT
      LAYER met3 ;
        RECT 446.000 360.440 450.000 361.040 ;
    END
  END wpg_st_addr[22]
  PIN wpg_st_addr[23]
    DIRECTION INPUT ;
    USE SIGNAL ;
    ANTENNAGATEAREA 0.560700 ;
    ANTENNADIFFAREA 0.434700 ;
    PORT
      LAYER met3 ;
        RECT 446.000 108.840 450.000 109.440 ;
    END
  END wpg_st_addr[23]
  PIN wpg_st_addr[24]
    DIRECTION INPUT ;
    USE SIGNAL ;
    ANTENNAGATEAREA 0.560700 ;
    ANTENNADIFFAREA 0.434700 ;
    PORT
      LAYER met3 ;
        RECT 446.000 367.240 450.000 367.840 ;
    END
  END wpg_st_addr[24]
  PIN wpg_st_addr[25]
    DIRECTION INPUT ;
    USE SIGNAL ;
    ANTENNAGATEAREA 0.560700 ;
    ANTENNADIFFAREA 0.434700 ;
    PORT
      LAYER met3 ;
        RECT 446.000 357.040 450.000 357.640 ;
    END
  END wpg_st_addr[25]
  PIN wpg_st_addr[26]
    DIRECTION INPUT ;
    USE SIGNAL ;
    ANTENNAGATEAREA 0.560700 ;
    ANTENNADIFFAREA 0.434700 ;
    PORT
      LAYER met3 ;
        RECT 446.000 115.640 450.000 116.240 ;
    END
  END wpg_st_addr[26]
  PIN wpg_st_addr[27]
    DIRECTION INPUT ;
    USE SIGNAL ;
    ANTENNAGATEAREA 0.560700 ;
    ANTENNADIFFAREA 0.434700 ;
    PORT
      LAYER met3 ;
        RECT 446.000 377.440 450.000 378.040 ;
    END
  END wpg_st_addr[27]
  PIN wpg_st_addr[28]
    DIRECTION INPUT ;
    USE SIGNAL ;
    ANTENNAGATEAREA 0.560700 ;
    ANTENNADIFFAREA 0.434700 ;
    PORT
      LAYER met3 ;
        RECT 446.000 74.840 450.000 75.440 ;
    END
  END wpg_st_addr[28]
  PIN wpg_st_addr[29]
    DIRECTION INPUT ;
    USE SIGNAL ;
    ANTENNAGATEAREA 0.560700 ;
    ANTENNADIFFAREA 0.434700 ;
    PORT
      LAYER met3 ;
        RECT 446.000 27.240 450.000 27.840 ;
    END
  END wpg_st_addr[29]
  PIN wpg_st_addr[2]
    DIRECTION INPUT ;
    USE SIGNAL ;
    ANTENNAGATEAREA 0.560700 ;
    ANTENNADIFFAREA 0.434700 ;
    PORT
      LAYER met3 ;
        RECT 446.000 210.840 450.000 211.440 ;
    END
  END wpg_st_addr[2]
  PIN wpg_st_addr[30]
    DIRECTION INPUT ;
    USE SIGNAL ;
    ANTENNAGATEAREA 0.560700 ;
    ANTENNADIFFAREA 0.434700 ;
    PORT
      LAYER met3 ;
        RECT 446.000 448.840 450.000 449.440 ;
    END
  END wpg_st_addr[30]
  PIN wpg_st_addr[31]
    DIRECTION INPUT ;
    USE SIGNAL ;
    ANTENNAGATEAREA 0.560700 ;
    ANTENNADIFFAREA 0.434700 ;
    PORT
      LAYER met3 ;
        RECT 446.000 119.040 450.000 119.640 ;
    END
  END wpg_st_addr[31]
  PIN wpg_st_addr[32]
    DIRECTION INPUT ;
    USE SIGNAL ;
    ANTENNAGATEAREA 0.995400 ;
    ANTENNADIFFAREA 0.869400 ;
    PORT
      LAYER met3 ;
        RECT 446.000 442.040 450.000 442.640 ;
    END
  END wpg_st_addr[32]
  PIN wpg_st_addr[33]
    DIRECTION INPUT ;
    USE SIGNAL ;
    ANTENNAGATEAREA 0.560700 ;
    ANTENNADIFFAREA 0.434700 ;
    PORT
      LAYER met3 ;
        RECT 446.000 425.040 450.000 425.640 ;
    END
  END wpg_st_addr[33]
  PIN wpg_st_addr[34]
    DIRECTION INPUT ;
    USE SIGNAL ;
    ANTENNAGATEAREA 0.560700 ;
    ANTENNADIFFAREA 0.434700 ;
    PORT
      LAYER met3 ;
        RECT 446.000 10.240 450.000 10.840 ;
    END
  END wpg_st_addr[34]
  PIN wpg_st_addr[35]
    DIRECTION INPUT ;
    USE SIGNAL ;
    ANTENNAGATEAREA 0.560700 ;
    ANTENNADIFFAREA 0.434700 ;
    PORT
      LAYER met3 ;
        RECT 446.000 57.840 450.000 58.440 ;
    END
  END wpg_st_addr[35]
  PIN wpg_st_addr[36]
    DIRECTION INPUT ;
    USE SIGNAL ;
    ANTENNAGATEAREA 0.560700 ;
    ANTENNADIFFAREA 0.434700 ;
    PORT
      LAYER met3 ;
        RECT 446.000 37.440 450.000 38.040 ;
    END
  END wpg_st_addr[36]
  PIN wpg_st_addr[37]
    DIRECTION INPUT ;
    USE SIGNAL ;
    ANTENNAGATEAREA 0.560700 ;
    ANTENNADIFFAREA 0.434700 ;
    PORT
      LAYER met3 ;
        RECT 446.000 98.640 450.000 99.240 ;
    END
  END wpg_st_addr[37]
  PIN wpg_st_addr[38]
    DIRECTION INPUT ;
    USE SIGNAL ;
    ANTENNAGATEAREA 0.560700 ;
    ANTENNADIFFAREA 0.434700 ;
    PORT
      LAYER met3 ;
        RECT 446.000 81.640 450.000 82.240 ;
    END
  END wpg_st_addr[38]
  PIN wpg_st_addr[39]
    DIRECTION INPUT ;
    USE SIGNAL ;
    ANTENNAGATEAREA 0.560700 ;
    ANTENNADIFFAREA 0.434700 ;
    PORT
      LAYER met3 ;
        RECT 446.000 64.640 450.000 65.240 ;
    END
  END wpg_st_addr[39]
  PIN wpg_st_addr[3]
    DIRECTION INPUT ;
    USE SIGNAL ;
    ANTENNAGATEAREA 0.560700 ;
    ANTENNADIFFAREA 0.434700 ;
    PORT
      LAYER met3 ;
        RECT 446.000 227.840 450.000 228.440 ;
    END
  END wpg_st_addr[3]
  PIN wpg_st_addr[40]
    DIRECTION INPUT ;
    USE SIGNAL ;
    ANTENNAGATEAREA 0.560700 ;
    ANTENNADIFFAREA 0.434700 ;
    PORT
      LAYER met3 ;
        RECT 446.000 95.240 450.000 95.840 ;
    END
  END wpg_st_addr[40]
  PIN wpg_st_addr[41]
    DIRECTION INPUT ;
    USE SIGNAL ;
    ANTENNAGATEAREA 0.560700 ;
    ANTENNADIFFAREA 0.434700 ;
    PORT
      LAYER met3 ;
        RECT 446.000 44.240 450.000 44.840 ;
    END
  END wpg_st_addr[41]
  PIN wpg_st_addr[42]
    DIRECTION INPUT ;
    USE SIGNAL ;
    ANTENNAGATEAREA 0.560700 ;
    ANTENNADIFFAREA 0.434700 ;
    PORT
      LAYER met3 ;
        RECT 446.000 34.040 450.000 34.640 ;
    END
  END wpg_st_addr[42]
  PIN wpg_st_addr[43]
    DIRECTION INPUT ;
    USE SIGNAL ;
    ANTENNAGATEAREA 0.560700 ;
    ANTENNADIFFAREA 0.434700 ;
    PORT
      LAYER met3 ;
        RECT 446.000 40.840 450.000 41.440 ;
    END
  END wpg_st_addr[43]
  PIN wpg_st_addr[44]
    DIRECTION INPUT ;
    USE SIGNAL ;
    ANTENNAGATEAREA 0.560700 ;
    ANTENNADIFFAREA 0.434700 ;
    PORT
      LAYER met3 ;
        RECT 446.000 380.840 450.000 381.440 ;
    END
  END wpg_st_addr[44]
  PIN wpg_st_addr[45]
    DIRECTION INPUT ;
    USE SIGNAL ;
    ANTENNAGATEAREA 0.560700 ;
    ANTENNADIFFAREA 0.434700 ;
    PORT
      LAYER met3 ;
        RECT 446.000 401.240 450.000 401.840 ;
    END
  END wpg_st_addr[45]
  PIN wpg_st_addr[46]
    DIRECTION INPUT ;
    USE SIGNAL ;
    ANTENNAGATEAREA 0.560700 ;
    ANTENNADIFFAREA 0.434700 ;
    PORT
      LAYER met3 ;
        RECT 446.000 394.440 450.000 395.040 ;
    END
  END wpg_st_addr[46]
  PIN wpg_st_addr[47]
    DIRECTION INPUT ;
    USE SIGNAL ;
    ANTENNAGATEAREA 0.560700 ;
    ANTENNADIFFAREA 0.434700 ;
    PORT
      LAYER met3 ;
        RECT 446.000 411.440 450.000 412.040 ;
    END
  END wpg_st_addr[47]
  PIN wpg_st_addr[48]
    DIRECTION INPUT ;
    USE SIGNAL ;
    ANTENNAGATEAREA 0.560700 ;
    ANTENNADIFFAREA 0.434700 ;
    PORT
      LAYER met3 ;
        RECT 446.000 418.240 450.000 418.840 ;
    END
  END wpg_st_addr[48]
  PIN wpg_st_addr[49]
    DIRECTION INPUT ;
    USE SIGNAL ;
    ANTENNAGATEAREA 0.560700 ;
    ANTENNADIFFAREA 0.434700 ;
    PORT
      LAYER met3 ;
        RECT 446.000 435.240 450.000 435.840 ;
    END
  END wpg_st_addr[49]
  PIN wpg_st_addr[4]
    DIRECTION INPUT ;
    USE SIGNAL ;
    ANTENNAGATEAREA 0.560700 ;
    ANTENNADIFFAREA 0.434700 ;
    PORT
      LAYER met3 ;
        RECT 446.000 204.040 450.000 204.640 ;
    END
  END wpg_st_addr[4]
  PIN wpg_st_addr[50]
    DIRECTION INPUT ;
    USE SIGNAL ;
    ANTENNAGATEAREA 0.560700 ;
    ANTENNADIFFAREA 0.434700 ;
    PORT
      LAYER met3 ;
        RECT 446.000 445.440 450.000 446.040 ;
    END
  END wpg_st_addr[50]
  PIN wpg_st_addr[5]
    DIRECTION INPUT ;
    USE SIGNAL ;
    ANTENNAGATEAREA 0.560700 ;
    ANTENNADIFFAREA 0.434700 ;
    PORT
      LAYER met3 ;
        RECT 446.000 132.640 450.000 133.240 ;
    END
  END wpg_st_addr[5]
  PIN wpg_st_addr[6]
    DIRECTION INPUT ;
    USE SIGNAL ;
    ANTENNAGATEAREA 0.560700 ;
    ANTENNADIFFAREA 0.434700 ;
    PORT
      LAYER met3 ;
        RECT 446.000 20.440 450.000 21.040 ;
    END
  END wpg_st_addr[6]
  PIN wpg_st_addr[7]
    DIRECTION INPUT ;
    USE SIGNAL ;
    ANTENNAGATEAREA 0.560700 ;
    ANTENNADIFFAREA 0.434700 ;
    PORT
      LAYER met3 ;
        RECT 446.000 384.240 450.000 384.840 ;
    END
  END wpg_st_addr[7]
  PIN wpg_st_addr[8]
    DIRECTION INPUT ;
    USE SIGNAL ;
    ANTENNAGATEAREA 0.560700 ;
    ANTENNADIFFAREA 0.434700 ;
    PORT
      LAYER met3 ;
        RECT 446.000 289.040 450.000 289.640 ;
    END
  END wpg_st_addr[8]
  PIN wpg_st_addr[9]
    DIRECTION INPUT ;
    USE SIGNAL ;
    ANTENNAGATEAREA 0.560700 ;
    ANTENNADIFFAREA 0.434700 ;
    PORT
      LAYER met3 ;
        RECT 446.000 363.840 450.000 364.440 ;
    END
  END wpg_st_addr[9]
  PIN wr_buff_empty[0]
    DIRECTION OUTPUT ;
    USE SIGNAL ;
    ANTENNADIFFAREA 0.340600 ;
    PORT
      LAYER met3 ;
        RECT 446.000 258.440 450.000 259.040 ;
    END
  END wr_buff_empty[0]
  PIN wr_buff_empty[1]
    DIRECTION OUTPUT ;
    USE SIGNAL ;
    ANTENNADIFFAREA 0.340600 ;
    PORT
      LAYER met3 ;
        RECT 0.000 231.240 4.000 231.840 ;
    END
  END wr_buff_empty[1]
  PIN wr_buff_empty[2]
    DIRECTION OUTPUT ;
    USE SIGNAL ;
    ANTENNADIFFAREA 0.340600 ;
    PORT
      LAYER met3 ;
        RECT 0.000 272.040 4.000 272.640 ;
    END
  END wr_buff_empty[2]
  PIN wr_buff_full[0]
    DIRECTION OUTPUT ;
    USE SIGNAL ;
    ANTENNADIFFAREA 0.340600 ;
    PORT
      LAYER met3 ;
        RECT 0.000 278.840 4.000 279.440 ;
    END
  END wr_buff_full[0]
  PIN wr_buff_full[1]
    DIRECTION OUTPUT ;
    USE SIGNAL ;
    ANTENNADIFFAREA 0.340600 ;
    PORT
      LAYER met3 ;
        RECT 0.000 282.240 4.000 282.840 ;
    END
  END wr_buff_full[1]
  PIN wr_buff_full[2]
    DIRECTION OUTPUT ;
    USE SIGNAL ;
    ANTENNADIFFAREA 0.340600 ;
    PORT
      LAYER met3 ;
        RECT 0.000 176.840 4.000 177.440 ;
    END
  END wr_buff_full[2]
  PIN wr_buff_wdata[0]
    DIRECTION INPUT ;
    USE SIGNAL ;
    ANTENNAGATEAREA 0.560700 ;
    ANTENNADIFFAREA 0.434700 ;
    PORT
      LAYER met3 ;
        RECT 0.000 241.440 4.000 242.040 ;
    END
  END wr_buff_wdata[0]
  PIN wr_buff_wdata[10]
    DIRECTION INPUT ;
    USE SIGNAL ;
    ANTENNAGATEAREA 0.560700 ;
    ANTENNADIFFAREA 0.434700 ;
    PORT
      LAYER met3 ;
        RECT 0.000 295.840 4.000 296.440 ;
    END
  END wr_buff_wdata[10]
  PIN wr_buff_wdata[11]
    DIRECTION INPUT ;
    USE SIGNAL ;
    ANTENNAGATEAREA 0.560700 ;
    ANTENNADIFFAREA 0.434700 ;
    PORT
      LAYER met3 ;
        RECT 0.000 258.440 4.000 259.040 ;
    END
  END wr_buff_wdata[11]
  PIN wr_buff_wdata[12]
    DIRECTION INPUT ;
    USE SIGNAL ;
    ANTENNAGATEAREA 0.560700 ;
    ANTENNADIFFAREA 0.434700 ;
    PORT
      LAYER met3 ;
        RECT 0.000 224.440 4.000 225.040 ;
    END
  END wr_buff_wdata[12]
  PIN wr_buff_wdata[13]
    DIRECTION INPUT ;
    USE SIGNAL ;
    ANTENNAGATEAREA 0.560700 ;
    ANTENNADIFFAREA 0.434700 ;
    PORT
      LAYER met3 ;
        RECT 0.000 244.840 4.000 245.440 ;
    END
  END wr_buff_wdata[13]
  PIN wr_buff_wdata[14]
    DIRECTION INPUT ;
    USE SIGNAL ;
    ANTENNAGATEAREA 0.560700 ;
    ANTENNADIFFAREA 0.434700 ;
    PORT
      LAYER met3 ;
        RECT 0.000 299.240 4.000 299.840 ;
    END
  END wr_buff_wdata[14]
  PIN wr_buff_wdata[15]
    DIRECTION INPUT ;
    USE SIGNAL ;
    ANTENNAGATEAREA 0.560700 ;
    ANTENNADIFFAREA 0.434700 ;
    PORT
      LAYER met3 ;
        RECT 0.000 210.840 4.000 211.440 ;
    END
  END wr_buff_wdata[15]
  PIN wr_buff_wdata[16]
    DIRECTION INPUT ;
    USE SIGNAL ;
    ANTENNAGATEAREA 0.560700 ;
    ANTENNADIFFAREA 0.434700 ;
    PORT
      LAYER met3 ;
        RECT 0.000 173.440 4.000 174.040 ;
    END
  END wr_buff_wdata[16]
  PIN wr_buff_wdata[17]
    DIRECTION INPUT ;
    USE SIGNAL ;
    ANTENNAGATEAREA 0.560700 ;
    ANTENNADIFFAREA 0.434700 ;
    PORT
      LAYER met3 ;
        RECT 0.000 197.240 4.000 197.840 ;
    END
  END wr_buff_wdata[17]
  PIN wr_buff_wdata[18]
    DIRECTION INPUT ;
    USE SIGNAL ;
    ANTENNAGATEAREA 0.560700 ;
    ANTENNADIFFAREA 0.434700 ;
    PORT
      LAYER met3 ;
        RECT 0.000 159.840 4.000 160.440 ;
    END
  END wr_buff_wdata[18]
  PIN wr_buff_wdata[19]
    DIRECTION INPUT ;
    USE SIGNAL ;
    ANTENNAGATEAREA 0.560700 ;
    ANTENNADIFFAREA 0.434700 ;
    PORT
      LAYER met3 ;
        RECT 0.000 193.840 4.000 194.440 ;
    END
  END wr_buff_wdata[19]
  PIN wr_buff_wdata[1]
    DIRECTION INPUT ;
    USE SIGNAL ;
    ANTENNAGATEAREA 0.560700 ;
    ANTENNADIFFAREA 0.434700 ;
    PORT
      LAYER met2 ;
        RECT 351.070 0.000 351.350 4.000 ;
    END
  END wr_buff_wdata[1]
  PIN wr_buff_wdata[20]
    DIRECTION INPUT ;
    USE SIGNAL ;
    ANTENNAGATEAREA 0.560700 ;
    ANTENNADIFFAREA 0.434700 ;
    PORT
      LAYER met3 ;
        RECT 0.000 170.040 4.000 170.640 ;
    END
  END wr_buff_wdata[20]
  PIN wr_buff_wdata[21]
    DIRECTION INPUT ;
    USE SIGNAL ;
    ANTENNAGATEAREA 0.560700 ;
    ANTENNADIFFAREA 0.434700 ;
    PORT
      LAYER met3 ;
        RECT 0.000 190.440 4.000 191.040 ;
    END
  END wr_buff_wdata[21]
  PIN wr_buff_wdata[22]
    DIRECTION INPUT ;
    USE SIGNAL ;
    ANTENNAGATEAREA 0.560700 ;
    ANTENNADIFFAREA 0.434700 ;
    PORT
      LAYER met3 ;
        RECT 0.000 187.040 4.000 187.640 ;
    END
  END wr_buff_wdata[22]
  PIN wr_buff_wdata[23]
    DIRECTION INPUT ;
    USE SIGNAL ;
    ANTENNAGATEAREA 0.560700 ;
    ANTENNADIFFAREA 0.434700 ;
    PORT
      LAYER met3 ;
        RECT 0.000 166.640 4.000 167.240 ;
    END
  END wr_buff_wdata[23]
  PIN wr_buff_wdata[2]
    DIRECTION INPUT ;
    USE SIGNAL ;
    ANTENNAGATEAREA 0.560700 ;
    ANTENNADIFFAREA 0.434700 ;
    PORT
      LAYER met2 ;
        RECT 376.830 0.000 377.110 4.000 ;
    END
  END wr_buff_wdata[2]
  PIN wr_buff_wdata[3]
    DIRECTION INPUT ;
    USE SIGNAL ;
    ANTENNAGATEAREA 0.560700 ;
    ANTENNADIFFAREA 0.434700 ;
    PORT
      LAYER met3 ;
        RECT 0.000 227.840 4.000 228.440 ;
    END
  END wr_buff_wdata[3]
  PIN wr_buff_wdata[4]
    DIRECTION INPUT ;
    USE SIGNAL ;
    ANTENNAGATEAREA 0.560700 ;
    ANTENNADIFFAREA 0.434700 ;
    PORT
      LAYER met2 ;
        RECT 380.050 0.000 380.330 4.000 ;
    END
  END wr_buff_wdata[4]
  PIN wr_buff_wdata[5]
    DIRECTION INPUT ;
    USE SIGNAL ;
    ANTENNAGATEAREA 0.560700 ;
    ANTENNADIFFAREA 0.434700 ;
    PORT
      LAYER met3 ;
        RECT 0.000 251.640 4.000 252.240 ;
    END
  END wr_buff_wdata[5]
  PIN wr_buff_wdata[6]
    DIRECTION INPUT ;
    USE SIGNAL ;
    ANTENNAGATEAREA 0.560700 ;
    ANTENNADIFFAREA 0.434700 ;
    PORT
      LAYER met2 ;
        RECT 373.610 0.000 373.890 4.000 ;
    END
  END wr_buff_wdata[6]
  PIN wr_buff_wdata[7]
    DIRECTION INPUT ;
    USE SIGNAL ;
    ANTENNAGATEAREA 0.560700 ;
    ANTENNADIFFAREA 0.434700 ;
    PORT
      LAYER met2 ;
        RECT 354.290 0.000 354.570 4.000 ;
    END
  END wr_buff_wdata[7]
  PIN wr_buff_wdata[8]
    DIRECTION INPUT ;
    USE SIGNAL ;
    ANTENNAGATEAREA 0.560700 ;
    ANTENNADIFFAREA 0.434700 ;
    PORT
      LAYER met3 ;
        RECT 0.000 214.240 4.000 214.840 ;
    END
  END wr_buff_wdata[8]
  PIN wr_buff_wdata[9]
    DIRECTION INPUT ;
    USE SIGNAL ;
    ANTENNAGATEAREA 0.560700 ;
    ANTENNADIFFAREA 0.434700 ;
    PORT
      LAYER met3 ;
        RECT 0.000 217.640 4.000 218.240 ;
    END
  END wr_buff_wdata[9]
  PIN wr_buff_wren[0]
    DIRECTION INPUT ;
    USE SIGNAL ;
    ANTENNAGATEAREA 0.560700 ;
    ANTENNADIFFAREA 0.434700 ;
    PORT
      LAYER met3 ;
        RECT 0.000 285.640 4.000 286.240 ;
    END
  END wr_buff_wren[0]
  PIN wr_buff_wren[1]
    DIRECTION INPUT ;
    USE SIGNAL ;
    ANTENNAGATEAREA 0.560700 ;
    ANTENNADIFFAREA 0.434700 ;
    PORT
      LAYER met3 ;
        RECT 0.000 255.040 4.000 255.640 ;
    END
  END wr_buff_wren[1]
  PIN wr_buff_wren[2]
    DIRECTION INPUT ;
    USE SIGNAL ;
    ANTENNAGATEAREA 0.560700 ;
    ANTENNADIFFAREA 0.434700 ;
    PORT
      LAYER met3 ;
        RECT 0.000 180.240 4.000 180.840 ;
    END
  END wr_buff_wren[2]
  OBS
      LAYER nwell ;
        RECT 5.330 10.760 444.550 438.110 ;
      LAYER li1 ;
        RECT 5.520 10.795 444.360 438.005 ;
      LAYER met1 ;
        RECT 0.070 7.180 447.970 446.720 ;
      LAYER met2 ;
        RECT 0.650 445.720 3.030 449.325 ;
        RECT 3.870 445.720 6.250 449.325 ;
        RECT 7.090 445.720 9.470 449.325 ;
        RECT 10.310 445.720 12.690 449.325 ;
        RECT 13.530 445.720 15.910 449.325 ;
        RECT 16.750 445.720 19.130 449.325 ;
        RECT 19.970 445.720 22.350 449.325 ;
        RECT 23.190 445.720 25.570 449.325 ;
        RECT 26.410 445.720 28.790 449.325 ;
        RECT 29.630 445.720 32.010 449.325 ;
        RECT 32.850 445.720 35.230 449.325 ;
        RECT 36.070 445.720 38.450 449.325 ;
        RECT 39.290 445.720 41.670 449.325 ;
        RECT 42.510 445.720 44.890 449.325 ;
        RECT 45.730 445.720 48.110 449.325 ;
        RECT 48.950 445.720 51.330 449.325 ;
        RECT 52.170 445.720 54.550 449.325 ;
        RECT 55.390 445.720 57.770 449.325 ;
        RECT 58.610 445.720 60.990 449.325 ;
        RECT 61.830 445.720 64.210 449.325 ;
        RECT 65.050 445.720 67.430 449.325 ;
        RECT 68.270 445.720 70.650 449.325 ;
        RECT 71.490 445.720 73.870 449.325 ;
        RECT 74.710 445.720 77.090 449.325 ;
        RECT 77.930 445.720 80.310 449.325 ;
        RECT 81.150 445.720 83.530 449.325 ;
        RECT 84.370 445.720 86.750 449.325 ;
        RECT 87.590 445.720 89.970 449.325 ;
        RECT 90.810 445.720 93.190 449.325 ;
        RECT 94.030 445.720 96.410 449.325 ;
        RECT 97.250 445.720 99.630 449.325 ;
        RECT 100.470 445.720 102.850 449.325 ;
        RECT 103.690 445.720 106.070 449.325 ;
        RECT 106.910 445.720 109.290 449.325 ;
        RECT 110.130 445.720 112.510 449.325 ;
        RECT 113.350 445.720 115.730 449.325 ;
        RECT 116.570 445.720 118.950 449.325 ;
        RECT 119.790 445.720 122.170 449.325 ;
        RECT 123.010 445.720 125.390 449.325 ;
        RECT 126.230 445.720 128.610 449.325 ;
        RECT 129.450 445.720 131.830 449.325 ;
        RECT 132.670 445.720 135.050 449.325 ;
        RECT 135.890 445.720 138.270 449.325 ;
        RECT 139.110 445.720 141.490 449.325 ;
        RECT 142.330 445.720 144.710 449.325 ;
        RECT 145.550 445.720 147.930 449.325 ;
        RECT 148.770 445.720 151.150 449.325 ;
        RECT 151.990 445.720 154.370 449.325 ;
        RECT 155.210 445.720 157.590 449.325 ;
        RECT 158.430 445.720 160.810 449.325 ;
        RECT 161.650 445.720 164.030 449.325 ;
        RECT 164.870 445.720 167.250 449.325 ;
        RECT 168.090 445.720 170.470 449.325 ;
        RECT 171.310 445.720 173.690 449.325 ;
        RECT 174.530 445.720 176.910 449.325 ;
        RECT 177.750 445.720 180.130 449.325 ;
        RECT 180.970 445.720 183.350 449.325 ;
        RECT 184.190 445.720 186.570 449.325 ;
        RECT 187.410 445.720 189.790 449.325 ;
        RECT 190.630 445.720 193.010 449.325 ;
        RECT 193.850 445.720 196.230 449.325 ;
        RECT 197.070 445.720 199.450 449.325 ;
        RECT 200.290 445.720 202.670 449.325 ;
        RECT 203.510 445.720 205.890 449.325 ;
        RECT 206.730 445.720 209.110 449.325 ;
        RECT 209.950 445.720 212.330 449.325 ;
        RECT 213.170 445.720 215.550 449.325 ;
        RECT 216.390 445.720 218.770 449.325 ;
        RECT 219.610 445.720 221.990 449.325 ;
        RECT 222.830 445.720 225.210 449.325 ;
        RECT 226.050 445.720 228.430 449.325 ;
        RECT 229.270 445.720 231.650 449.325 ;
        RECT 232.490 445.720 234.870 449.325 ;
        RECT 235.710 445.720 238.090 449.325 ;
        RECT 238.930 445.720 241.310 449.325 ;
        RECT 242.150 445.720 244.530 449.325 ;
        RECT 245.370 445.720 247.750 449.325 ;
        RECT 248.590 445.720 250.970 449.325 ;
        RECT 251.810 445.720 254.190 449.325 ;
        RECT 255.030 445.720 257.410 449.325 ;
        RECT 258.250 445.720 260.630 449.325 ;
        RECT 261.470 445.720 263.850 449.325 ;
        RECT 264.690 445.720 267.070 449.325 ;
        RECT 267.910 445.720 270.290 449.325 ;
        RECT 271.130 445.720 273.510 449.325 ;
        RECT 274.350 445.720 276.730 449.325 ;
        RECT 277.570 445.720 279.950 449.325 ;
        RECT 280.790 445.720 283.170 449.325 ;
        RECT 284.010 445.720 286.390 449.325 ;
        RECT 287.230 445.720 289.610 449.325 ;
        RECT 290.450 445.720 292.830 449.325 ;
        RECT 293.670 445.720 296.050 449.325 ;
        RECT 296.890 445.720 299.270 449.325 ;
        RECT 300.110 445.720 302.490 449.325 ;
        RECT 303.330 445.720 305.710 449.325 ;
        RECT 306.550 445.720 308.930 449.325 ;
        RECT 309.770 445.720 312.150 449.325 ;
        RECT 312.990 445.720 315.370 449.325 ;
        RECT 316.210 445.720 318.590 449.325 ;
        RECT 319.430 445.720 321.810 449.325 ;
        RECT 322.650 445.720 325.030 449.325 ;
        RECT 325.870 445.720 328.250 449.325 ;
        RECT 329.090 445.720 331.470 449.325 ;
        RECT 332.310 445.720 334.690 449.325 ;
        RECT 335.530 445.720 337.910 449.325 ;
        RECT 338.750 445.720 341.130 449.325 ;
        RECT 341.970 445.720 344.350 449.325 ;
        RECT 345.190 445.720 347.570 449.325 ;
        RECT 348.410 445.720 350.790 449.325 ;
        RECT 351.630 445.720 354.010 449.325 ;
        RECT 354.850 445.720 357.230 449.325 ;
        RECT 358.070 445.720 360.450 449.325 ;
        RECT 361.290 445.720 363.670 449.325 ;
        RECT 364.510 445.720 366.890 449.325 ;
        RECT 367.730 445.720 370.110 449.325 ;
        RECT 370.950 445.720 373.330 449.325 ;
        RECT 374.170 445.720 376.550 449.325 ;
        RECT 377.390 445.720 379.770 449.325 ;
        RECT 380.610 445.720 382.990 449.325 ;
        RECT 383.830 445.720 386.210 449.325 ;
        RECT 387.050 445.720 389.430 449.325 ;
        RECT 390.270 445.720 392.650 449.325 ;
        RECT 393.490 445.720 395.870 449.325 ;
        RECT 396.710 445.720 399.090 449.325 ;
        RECT 399.930 445.720 402.310 449.325 ;
        RECT 403.150 445.720 405.530 449.325 ;
        RECT 406.370 445.720 408.750 449.325 ;
        RECT 409.590 445.720 411.970 449.325 ;
        RECT 412.810 445.720 415.190 449.325 ;
        RECT 416.030 445.720 418.410 449.325 ;
        RECT 419.250 445.720 421.630 449.325 ;
        RECT 422.470 445.720 424.850 449.325 ;
        RECT 425.690 445.720 428.070 449.325 ;
        RECT 428.910 445.720 431.290 449.325 ;
        RECT 432.130 445.720 434.510 449.325 ;
        RECT 435.350 445.720 437.730 449.325 ;
        RECT 438.570 445.720 440.950 449.325 ;
        RECT 441.790 445.720 444.170 449.325 ;
        RECT 445.010 445.720 447.390 449.325 ;
        RECT 0.100 4.280 447.940 445.720 ;
        RECT 0.100 0.155 122.170 4.280 ;
        RECT 123.010 0.155 125.390 4.280 ;
        RECT 126.230 0.155 128.610 4.280 ;
        RECT 129.450 0.155 131.830 4.280 ;
        RECT 132.670 0.155 135.050 4.280 ;
        RECT 135.890 0.155 154.370 4.280 ;
        RECT 155.210 0.155 157.590 4.280 ;
        RECT 158.430 0.155 160.810 4.280 ;
        RECT 161.650 0.155 164.030 4.280 ;
        RECT 164.870 0.155 167.250 4.280 ;
        RECT 168.090 0.155 170.470 4.280 ;
        RECT 171.310 0.155 173.690 4.280 ;
        RECT 174.530 0.155 180.130 4.280 ;
        RECT 180.970 0.155 196.230 4.280 ;
        RECT 197.070 0.155 199.450 4.280 ;
        RECT 200.290 0.155 202.670 4.280 ;
        RECT 203.510 0.155 205.890 4.280 ;
        RECT 206.730 0.155 209.110 4.280 ;
        RECT 209.950 0.155 218.770 4.280 ;
        RECT 219.610 0.155 221.990 4.280 ;
        RECT 222.830 0.155 289.610 4.280 ;
        RECT 290.450 0.155 292.830 4.280 ;
        RECT 293.670 0.155 296.050 4.280 ;
        RECT 296.890 0.155 299.270 4.280 ;
        RECT 300.110 0.155 302.490 4.280 ;
        RECT 303.330 0.155 308.930 4.280 ;
        RECT 309.770 0.155 312.150 4.280 ;
        RECT 312.990 0.155 315.370 4.280 ;
        RECT 316.210 0.155 325.030 4.280 ;
        RECT 325.870 0.155 350.790 4.280 ;
        RECT 351.630 0.155 354.010 4.280 ;
        RECT 354.850 0.155 373.330 4.280 ;
        RECT 374.170 0.155 376.550 4.280 ;
        RECT 377.390 0.155 379.770 4.280 ;
        RECT 380.610 0.155 447.940 4.280 ;
      LAYER met3 ;
        RECT 2.365 448.440 445.600 449.305 ;
        RECT 2.365 446.440 446.000 448.440 ;
        RECT 2.365 445.040 445.600 446.440 ;
        RECT 2.365 443.040 446.000 445.040 ;
        RECT 2.365 441.640 445.600 443.040 ;
        RECT 2.365 439.640 446.000 441.640 ;
        RECT 2.365 438.240 445.600 439.640 ;
        RECT 2.365 436.240 446.000 438.240 ;
        RECT 2.365 434.840 445.600 436.240 ;
        RECT 2.365 432.840 446.000 434.840 ;
        RECT 2.365 431.440 445.600 432.840 ;
        RECT 2.365 429.440 446.000 431.440 ;
        RECT 2.365 428.040 445.600 429.440 ;
        RECT 2.365 426.040 446.000 428.040 ;
        RECT 4.400 424.640 445.600 426.040 ;
        RECT 2.365 422.640 446.000 424.640 ;
        RECT 4.400 421.240 445.600 422.640 ;
        RECT 2.365 419.240 446.000 421.240 ;
        RECT 4.400 417.840 445.600 419.240 ;
        RECT 2.365 415.840 446.000 417.840 ;
        RECT 4.400 414.440 445.600 415.840 ;
        RECT 2.365 412.440 446.000 414.440 ;
        RECT 4.400 411.040 445.600 412.440 ;
        RECT 2.365 409.040 446.000 411.040 ;
        RECT 4.400 407.640 445.600 409.040 ;
        RECT 2.365 405.640 446.000 407.640 ;
        RECT 4.400 404.240 445.600 405.640 ;
        RECT 2.365 402.240 446.000 404.240 ;
        RECT 4.400 400.840 445.600 402.240 ;
        RECT 2.365 398.840 446.000 400.840 ;
        RECT 4.400 397.440 445.600 398.840 ;
        RECT 2.365 395.440 446.000 397.440 ;
        RECT 4.400 394.040 445.600 395.440 ;
        RECT 2.365 392.040 446.000 394.040 ;
        RECT 4.400 390.640 445.600 392.040 ;
        RECT 2.365 388.640 446.000 390.640 ;
        RECT 4.400 387.240 445.600 388.640 ;
        RECT 2.365 385.240 446.000 387.240 ;
        RECT 4.400 383.840 445.600 385.240 ;
        RECT 2.365 381.840 446.000 383.840 ;
        RECT 4.400 380.440 445.600 381.840 ;
        RECT 2.365 378.440 446.000 380.440 ;
        RECT 4.400 377.040 445.600 378.440 ;
        RECT 2.365 375.040 446.000 377.040 ;
        RECT 4.400 373.640 445.600 375.040 ;
        RECT 2.365 371.640 446.000 373.640 ;
        RECT 4.400 370.240 445.600 371.640 ;
        RECT 2.365 368.240 446.000 370.240 ;
        RECT 4.400 366.840 445.600 368.240 ;
        RECT 2.365 364.840 446.000 366.840 ;
        RECT 4.400 363.440 445.600 364.840 ;
        RECT 2.365 361.440 446.000 363.440 ;
        RECT 4.400 360.040 445.600 361.440 ;
        RECT 2.365 358.040 446.000 360.040 ;
        RECT 4.400 356.640 445.600 358.040 ;
        RECT 2.365 354.640 446.000 356.640 ;
        RECT 4.400 353.240 445.600 354.640 ;
        RECT 2.365 351.240 446.000 353.240 ;
        RECT 4.400 349.840 445.600 351.240 ;
        RECT 2.365 347.840 446.000 349.840 ;
        RECT 4.400 346.440 445.600 347.840 ;
        RECT 2.365 344.440 446.000 346.440 ;
        RECT 4.400 343.040 445.600 344.440 ;
        RECT 2.365 341.040 446.000 343.040 ;
        RECT 4.400 339.640 445.600 341.040 ;
        RECT 2.365 337.640 446.000 339.640 ;
        RECT 4.400 336.240 445.600 337.640 ;
        RECT 2.365 334.240 446.000 336.240 ;
        RECT 4.400 332.840 445.600 334.240 ;
        RECT 2.365 330.840 446.000 332.840 ;
        RECT 4.400 329.440 445.600 330.840 ;
        RECT 2.365 327.440 446.000 329.440 ;
        RECT 4.400 326.040 445.600 327.440 ;
        RECT 2.365 324.040 446.000 326.040 ;
        RECT 4.400 322.640 445.600 324.040 ;
        RECT 2.365 320.640 446.000 322.640 ;
        RECT 4.400 319.240 445.600 320.640 ;
        RECT 2.365 317.240 446.000 319.240 ;
        RECT 4.400 315.840 445.600 317.240 ;
        RECT 2.365 313.840 446.000 315.840 ;
        RECT 4.400 312.440 445.600 313.840 ;
        RECT 2.365 310.440 446.000 312.440 ;
        RECT 4.400 309.040 445.600 310.440 ;
        RECT 2.365 307.040 446.000 309.040 ;
        RECT 4.400 305.640 445.600 307.040 ;
        RECT 2.365 303.640 446.000 305.640 ;
        RECT 4.400 302.240 445.600 303.640 ;
        RECT 2.365 300.240 446.000 302.240 ;
        RECT 4.400 298.840 445.600 300.240 ;
        RECT 2.365 296.840 446.000 298.840 ;
        RECT 4.400 295.440 445.600 296.840 ;
        RECT 2.365 293.440 446.000 295.440 ;
        RECT 4.400 292.040 445.600 293.440 ;
        RECT 2.365 290.040 446.000 292.040 ;
        RECT 4.400 288.640 445.600 290.040 ;
        RECT 2.365 286.640 446.000 288.640 ;
        RECT 4.400 285.240 445.600 286.640 ;
        RECT 2.365 283.240 446.000 285.240 ;
        RECT 4.400 281.840 445.600 283.240 ;
        RECT 2.365 279.840 446.000 281.840 ;
        RECT 4.400 278.440 445.600 279.840 ;
        RECT 2.365 276.440 446.000 278.440 ;
        RECT 4.400 275.040 445.600 276.440 ;
        RECT 2.365 273.040 446.000 275.040 ;
        RECT 4.400 271.640 445.600 273.040 ;
        RECT 2.365 269.640 446.000 271.640 ;
        RECT 4.400 268.240 445.600 269.640 ;
        RECT 2.365 266.240 446.000 268.240 ;
        RECT 4.400 264.840 445.600 266.240 ;
        RECT 2.365 262.840 446.000 264.840 ;
        RECT 4.400 261.440 445.600 262.840 ;
        RECT 2.365 259.440 446.000 261.440 ;
        RECT 4.400 258.040 445.600 259.440 ;
        RECT 2.365 256.040 446.000 258.040 ;
        RECT 4.400 254.640 445.600 256.040 ;
        RECT 2.365 252.640 446.000 254.640 ;
        RECT 4.400 251.240 445.600 252.640 ;
        RECT 2.365 249.240 446.000 251.240 ;
        RECT 4.400 247.840 445.600 249.240 ;
        RECT 2.365 245.840 446.000 247.840 ;
        RECT 4.400 244.440 445.600 245.840 ;
        RECT 2.365 242.440 446.000 244.440 ;
        RECT 4.400 241.040 445.600 242.440 ;
        RECT 2.365 239.040 446.000 241.040 ;
        RECT 4.400 237.640 445.600 239.040 ;
        RECT 2.365 235.640 446.000 237.640 ;
        RECT 4.400 234.240 445.600 235.640 ;
        RECT 2.365 232.240 446.000 234.240 ;
        RECT 4.400 230.840 445.600 232.240 ;
        RECT 2.365 228.840 446.000 230.840 ;
        RECT 4.400 227.440 445.600 228.840 ;
        RECT 2.365 225.440 446.000 227.440 ;
        RECT 4.400 224.040 445.600 225.440 ;
        RECT 2.365 222.040 446.000 224.040 ;
        RECT 4.400 220.640 445.600 222.040 ;
        RECT 2.365 218.640 446.000 220.640 ;
        RECT 4.400 217.240 445.600 218.640 ;
        RECT 2.365 215.240 446.000 217.240 ;
        RECT 4.400 213.840 445.600 215.240 ;
        RECT 2.365 211.840 446.000 213.840 ;
        RECT 4.400 210.440 445.600 211.840 ;
        RECT 2.365 208.440 446.000 210.440 ;
        RECT 4.400 207.040 445.600 208.440 ;
        RECT 2.365 205.040 446.000 207.040 ;
        RECT 4.400 203.640 445.600 205.040 ;
        RECT 2.365 201.640 446.000 203.640 ;
        RECT 4.400 200.240 445.600 201.640 ;
        RECT 2.365 198.240 446.000 200.240 ;
        RECT 4.400 196.840 445.600 198.240 ;
        RECT 2.365 194.840 446.000 196.840 ;
        RECT 4.400 193.440 445.600 194.840 ;
        RECT 2.365 191.440 446.000 193.440 ;
        RECT 4.400 190.040 445.600 191.440 ;
        RECT 2.365 188.040 446.000 190.040 ;
        RECT 4.400 186.640 445.600 188.040 ;
        RECT 2.365 184.640 446.000 186.640 ;
        RECT 4.400 183.240 445.600 184.640 ;
        RECT 2.365 181.240 446.000 183.240 ;
        RECT 4.400 179.840 445.600 181.240 ;
        RECT 2.365 177.840 446.000 179.840 ;
        RECT 4.400 176.440 445.600 177.840 ;
        RECT 2.365 174.440 446.000 176.440 ;
        RECT 4.400 173.040 445.600 174.440 ;
        RECT 2.365 171.040 446.000 173.040 ;
        RECT 4.400 169.640 445.600 171.040 ;
        RECT 2.365 167.640 446.000 169.640 ;
        RECT 4.400 166.240 445.600 167.640 ;
        RECT 2.365 164.240 446.000 166.240 ;
        RECT 2.365 162.840 445.600 164.240 ;
        RECT 2.365 160.840 446.000 162.840 ;
        RECT 4.400 159.440 445.600 160.840 ;
        RECT 2.365 157.440 446.000 159.440 ;
        RECT 2.365 156.040 445.600 157.440 ;
        RECT 2.365 154.040 446.000 156.040 ;
        RECT 2.365 152.640 445.600 154.040 ;
        RECT 2.365 150.640 446.000 152.640 ;
        RECT 2.365 149.240 445.600 150.640 ;
        RECT 2.365 147.240 446.000 149.240 ;
        RECT 2.365 145.840 445.600 147.240 ;
        RECT 2.365 143.840 446.000 145.840 ;
        RECT 2.365 142.440 445.600 143.840 ;
        RECT 2.365 140.440 446.000 142.440 ;
        RECT 2.365 139.040 445.600 140.440 ;
        RECT 2.365 137.040 446.000 139.040 ;
        RECT 2.365 135.640 445.600 137.040 ;
        RECT 2.365 133.640 446.000 135.640 ;
        RECT 2.365 132.240 445.600 133.640 ;
        RECT 2.365 130.240 446.000 132.240 ;
        RECT 2.365 128.840 445.600 130.240 ;
        RECT 2.365 126.840 446.000 128.840 ;
        RECT 2.365 125.440 445.600 126.840 ;
        RECT 2.365 123.440 446.000 125.440 ;
        RECT 2.365 122.040 445.600 123.440 ;
        RECT 2.365 120.040 446.000 122.040 ;
        RECT 2.365 118.640 445.600 120.040 ;
        RECT 2.365 116.640 446.000 118.640 ;
        RECT 2.365 115.240 445.600 116.640 ;
        RECT 2.365 113.240 446.000 115.240 ;
        RECT 2.365 111.840 445.600 113.240 ;
        RECT 2.365 109.840 446.000 111.840 ;
        RECT 2.365 108.440 445.600 109.840 ;
        RECT 2.365 106.440 446.000 108.440 ;
        RECT 2.365 105.040 445.600 106.440 ;
        RECT 2.365 103.040 446.000 105.040 ;
        RECT 2.365 101.640 445.600 103.040 ;
        RECT 2.365 99.640 446.000 101.640 ;
        RECT 2.365 98.240 445.600 99.640 ;
        RECT 2.365 96.240 446.000 98.240 ;
        RECT 2.365 94.840 445.600 96.240 ;
        RECT 2.365 92.840 446.000 94.840 ;
        RECT 2.365 91.440 445.600 92.840 ;
        RECT 2.365 89.440 446.000 91.440 ;
        RECT 2.365 88.040 445.600 89.440 ;
        RECT 2.365 86.040 446.000 88.040 ;
        RECT 2.365 84.640 445.600 86.040 ;
        RECT 2.365 82.640 446.000 84.640 ;
        RECT 2.365 81.240 445.600 82.640 ;
        RECT 2.365 79.240 446.000 81.240 ;
        RECT 2.365 77.840 445.600 79.240 ;
        RECT 2.365 75.840 446.000 77.840 ;
        RECT 2.365 74.440 445.600 75.840 ;
        RECT 2.365 72.440 446.000 74.440 ;
        RECT 2.365 71.040 445.600 72.440 ;
        RECT 2.365 69.040 446.000 71.040 ;
        RECT 2.365 67.640 445.600 69.040 ;
        RECT 2.365 65.640 446.000 67.640 ;
        RECT 2.365 64.240 445.600 65.640 ;
        RECT 2.365 62.240 446.000 64.240 ;
        RECT 2.365 60.840 445.600 62.240 ;
        RECT 2.365 58.840 446.000 60.840 ;
        RECT 2.365 57.440 445.600 58.840 ;
        RECT 2.365 55.440 446.000 57.440 ;
        RECT 2.365 54.040 445.600 55.440 ;
        RECT 2.365 52.040 446.000 54.040 ;
        RECT 2.365 50.640 445.600 52.040 ;
        RECT 2.365 48.640 446.000 50.640 ;
        RECT 2.365 47.240 445.600 48.640 ;
        RECT 2.365 45.240 446.000 47.240 ;
        RECT 2.365 43.840 445.600 45.240 ;
        RECT 2.365 41.840 446.000 43.840 ;
        RECT 2.365 40.440 445.600 41.840 ;
        RECT 2.365 38.440 446.000 40.440 ;
        RECT 2.365 37.040 445.600 38.440 ;
        RECT 2.365 35.040 446.000 37.040 ;
        RECT 2.365 33.640 445.600 35.040 ;
        RECT 2.365 31.640 446.000 33.640 ;
        RECT 2.365 30.240 445.600 31.640 ;
        RECT 2.365 28.240 446.000 30.240 ;
        RECT 2.365 26.840 445.600 28.240 ;
        RECT 2.365 24.840 446.000 26.840 ;
        RECT 2.365 23.440 445.600 24.840 ;
        RECT 2.365 21.440 446.000 23.440 ;
        RECT 2.365 20.040 445.600 21.440 ;
        RECT 2.365 18.040 446.000 20.040 ;
        RECT 2.365 16.640 445.600 18.040 ;
        RECT 2.365 14.640 446.000 16.640 ;
        RECT 2.365 13.240 445.600 14.640 ;
        RECT 2.365 11.240 446.000 13.240 ;
        RECT 2.365 9.840 445.600 11.240 ;
        RECT 2.365 7.840 446.000 9.840 ;
        RECT 2.365 6.440 445.600 7.840 ;
        RECT 2.365 4.440 446.000 6.440 ;
        RECT 2.365 3.040 445.600 4.440 ;
        RECT 2.365 1.040 446.000 3.040 ;
        RECT 2.365 0.175 445.600 1.040 ;
      LAYER met4 ;
        RECT 4.895 438.560 437.625 446.585 ;
        RECT 4.895 26.695 20.640 438.560 ;
        RECT 23.040 26.695 23.940 438.560 ;
        RECT 26.340 26.695 174.240 438.560 ;
        RECT 176.640 26.695 177.540 438.560 ;
        RECT 179.940 26.695 327.840 438.560 ;
        RECT 330.240 26.695 331.140 438.560 ;
        RECT 333.540 26.695 437.625 438.560 ;
  END
END mem_sys
END LIBRARY

